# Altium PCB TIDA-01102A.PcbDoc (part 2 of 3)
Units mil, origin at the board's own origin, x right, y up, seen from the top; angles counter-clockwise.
Board outline 4000 x 5050 mil, 4 copper layers (Top Layer, Mid-Layer 1, Mid-Layer 2, Bottom Layer), stack 29.3 mil thick; 176 components, 125 nets, 880 pads, 275 vias.

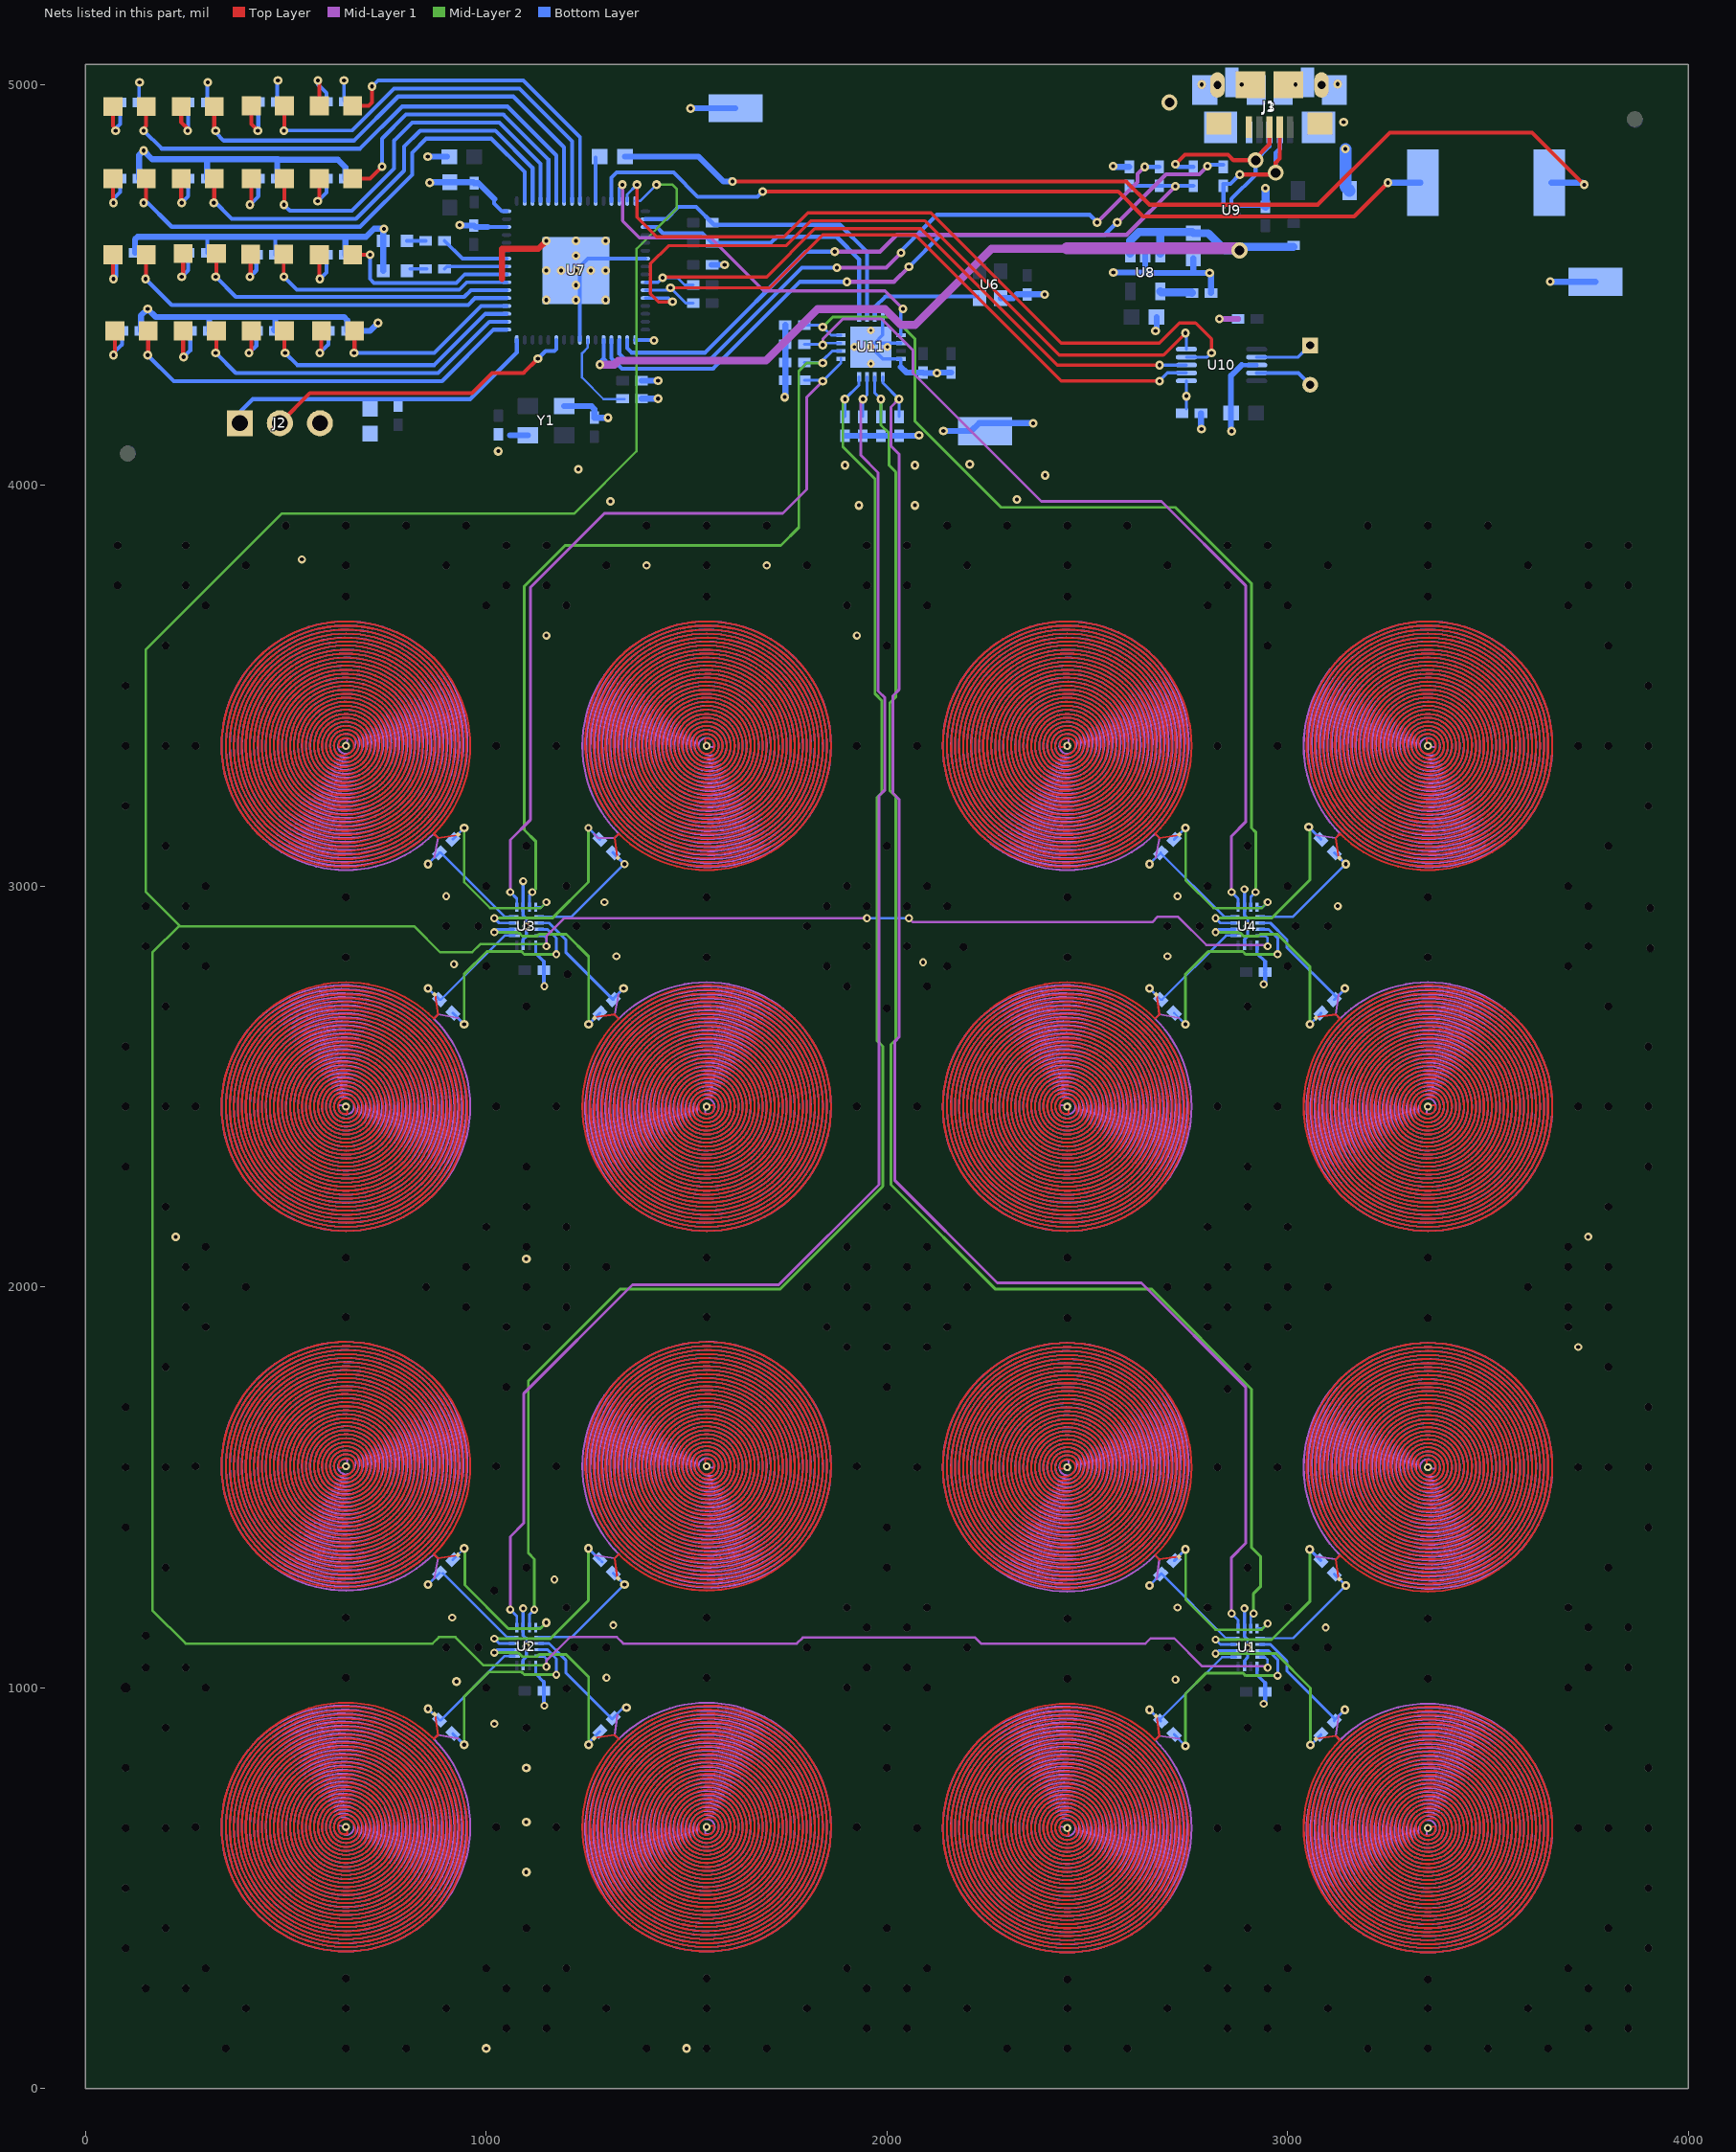
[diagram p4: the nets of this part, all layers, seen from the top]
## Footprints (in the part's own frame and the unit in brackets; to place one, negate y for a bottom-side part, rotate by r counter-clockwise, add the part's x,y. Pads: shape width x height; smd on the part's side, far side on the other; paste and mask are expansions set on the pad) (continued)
PRINTED_COIL_16MM_2_LAYER#7 [mil]
  round 20 hole 10: 2(0,0)
  round 8 smd: 2(355,40)
  Top Layer lines w5: 355,40 325,0 310,0 ccw(c0,0) 0,310 ; -0.05,-310 cw(c-0.6,0.05) -310,20.05 ; -0.21,-310.01 ccw(c-9.95,-0.21) 300,-0.21 ; 300,0 ccw(c0,0) 0,-300 ; -0.11,-300 ccw(c-10.06,-0.11) 0,-300 ; 0.23,-289.99 ccw(c-9.89,-0.28) 280,0.23 ; 290,-0.11 cw(c-10.06,-0.11) 0,-300 ; 290,0 ccw(c0,0) 0,-290 ; 280,0 ccw(c0,0) 0,-280 ; -0.2,-280.01 ccw(c-9.97,-0.2) 270,-0.2 ; 270,0 ccw(c0,0) 0,-270 ; -0.15,-270.01 ccw(c-10.04,-0.15) 260,-0.15 ; 260,0 ccw(c0,0) 0,-260 ; -0.11,-260 ccw(c-10.09,-0.11) 250,-0.11 ; 0.13,-249.99 ccw(c-9.89,-0.3) 240,0.13 ; 250,0 ccw(c0,0) 0,-250 ; 0.13,-239.99 ccw(c-9.92,-0.29) 230,0.13 ; 240,0 ccw(c0,0) 0,-240 ; 0.11,-230 ccw(c-9.92,-0.29) 220,0.11 ; 230,0 ccw(c0,0) 0,-230 ; 0.07,-220 ccw(c-9.91,-0.32) 210,0.07 ; 220,0 ccw(c0,0) 0,-220 ; 210,0 ccw(c0,0) 0,-210 ; -0.17,-210.01 ccw(c-10.07,-0.17) 200,-0.17 ; 0.11,-199.99 ccw(c-10.01,-0.24) 190,0.11 ; 200,0 ccw(c0,0) 0,-200 ; 190,0 ccw(c0,0) 0,-190 ccw(c-9.93,-0.33) 180,0.01 ccw(c0,0) -180,0 ccw(c0.07,0) -4.96,-180 ; -5.04,-180 ccw(c-10.07,0) 170,0 ccw(c0,0) -170,0 ccw(c0.08,0) -4.97,-170 ; -5.03,-170 ccw(c-10.08,0) 160,0 ccw(c0,0) 0,-160 ccw(c-10.04,-0.27) 150,0.01 ccw(c0,0) 0,-150 ; -0.07,-150 ccw(c-10.01,-0.33) 140,-0.07 ; 0.07,-139.99 ccw(c-9.93,-0.42) 130,0.07 ; 140,0 ccw(c0,0) 0,-140 ; 0.02,-130 ccw(c-9.95,-0.43) 120,0.02 ccw(c0,0) 0,-120 ccw(c-10.02,-0.4) 110,0.02 ; 130,0 ccw(c0,0) 0,-130 ; 110,0 ccw(c0,0) 0,-110 ; -0.05,-110 ccw(c-10.02,-0.43) 100,-0.05 ; 0.06,-99.99 ccw(c-10.05,-0.46) 90,0.06 ; 100,0 ccw(c0,0) 0,-100 ; 90,0 ccw(c0,0) 0,-90 ; 0.03,-90 ccw(c-10,-0.56) 80,0.07 ; 80,0 ccw(c0,0) 0,-80 ; -0.11,-80.01 ccw(c-10,-0.63) 70,-0.07 ; 70,0 ccw(c0,0) 0,-70 ccw(c-10,-0.72) 60,0.02 ; 60,0 ccw(c0,0) 0,-60 ; 0.01,-60 ccw(c-10,-0.83) 50,0.01 ccw(c0,0) 0,-50 ; 0.06,-49.99 ccw(c-9.99,-1.01) 40,0.04 ; 40,0 ccw(c0,0) 0,-40 ; -0.02,-40.01 ccw(c-9.96,-1.28) 30,-0.02 ; 30,0 ccw(c0,0) 0,-30 ; -0.04,-30.01 ccw(c-9.95,-1.7) 20,-0.02 ccw(c0,0) -20,0 ccw(c0.76,3) -10.01,-14.99 ; -10,-15 ccw(c-42.14,17.26) -0.01,-0.02 ; -0.05,310 ccw(c-0.59,-0.06) -310,19.95
  Mid-Layer 1 lines w5: 355,-40 325,0 310,0 cw(c0,0) 0,-310 ; -0.05,-310 cw(c-0.59,0.06) -310,-19.95 ; 300,0 cw(c0,0) 0,300 ; 300,0.21 ccw(c-9.95,0.21) -0.21,310.01 ; 290,0 cw(c0,0) 0,290 ; 290,0.11 ccw(c-10.06,0.11) -0.11,300 ; 280,-0.23 ccw(c-9.89,0.28) 0.23,289.99 ; 280,0 cw(c0,0) 0,280 ; 270,0 cw(c0,0) 0,270 ; 270,0.2 ccw(c-9.97,0.2) -0.2,280.01 ; 260,0 cw(c0,0) 0,260 ; 260,0.15 ccw(c-10.04,0.15) -0.15,270.01 ; 250,0 cw(c0,0) 0,250 ; 250,0.11 ccw(c-10.09,0.11) -0.11,260 ; 240,-0.13 ccw(c-9.89,0.3) 0.13,249.99 ; 240,0 cw(c0,0) 0,240 ; 230,-0.13 ccw(c-9.92,0.29) 0.13,239.99 ; 230,0 cw(c0,0) 0,230 ; 220,-0.11 ccw(c-9.92,0.29) 0.11,230 ; 220,0 cw(c0,0) 0,220 ; 210,-0.07 ccw(c-9.91,0.32) 0.07,220 ; 210,0 cw(c0,0) 0,210 ; 200,0 cw(c0,0) 0,200 ; 200,0.17 ccw(c-10.07,0.17) -0.17,210.01 ; 190,-0.11 ccw(c-10.01,0.24) 0.11,199.99 ; 190,0 cw(c0,0) 0,190 cw(c-9.93,0.33) 180,-0.01 ; 180,0 cw(c0,0) -180,0 cw(c0.07,0) -4.96,180 ; 140,0 cw(c0,0) 0,140 ; 140,0.07 ccw(c-10.01,0.33) -0.07,150 ; 130,-0.07 ccw(c-9.93,0.42) 0.07,139.99 ; 130,0 cw(c0,0) 0,130 ; 110,0 cw(c0,0) 0,110 ; 110,-0.02 ccw(c-10.02,0.4) 0.02,120 ccw(c0,0) 120,0 ccw(c-9.95,0.43) 0.02,130 ; 100,0.05 ccw(c-10.02,0.43) -0.05,110 ; 100,0 cw(c0,0) 0,100 ; 90,-0.07 ccw(c-10.05,0.46) 0.06,99.99 ; 90,0 cw(c0,0) 0,90 ; 80,-0.07 ccw(c-10,0.56) 0.03,90 ; 80,0 cw(c0,0) 0,80 ; 70,0 cw(c0,0) 0,70 cw(c-10,0.72) 60,-0.02 ; 70,0.07 ccw(c-10,0.63) -0.11,80.01 ; 60,0 cw(c0,0) 0,60 ; 40,0 cw(c0,0) 0,40 ; 40,-0.04 ccw(c-9.99,1.01) 0.06,49.99 ; 30,0.02 ccw(c-9.96,1.28) -0.02,40.01 ; 30,0 cw(c0,0) 0,30 ; -0.01,0.02 ccw(c-42.14,-17.26) -10,15 ; -10.01,14.99 ccw(c0.76,-3) -20,-0.01 ccw(c0,0) 20,0 ccw(c-9.95,1.7) -0.04,30.01 ; 0,50 ccw(c0,0) 50,0 ccw(c-10,0.83) 0.01,60 ; 0,150 ccw(c0,0) 150,0 ccw(c-10.04,0.27) 0.01,160 ccw(c0,0) 160,0 ccw(c-10.08,0) -5.03,170 ; -4.97,170 ccw(c0.08,0) -170,0 ccw(c0,0) 170,0 ccw(c-10.07,0) -5.04,180 ; -310,-20.05 cw(c-0.6,-0.05) -0.05,310
RGC0064B [mm]
  oval 0.6x0.24 smd mask+0.07: 1(-4.4,3.75) 2(-4.4,3.25) 3(-4.4,2.75) 4(-4.4,2.25) 5(-4.4,1.75) 6(-4.4,1.25) 7(-4.4,0.75) 8(-4.4,0.25) 9(-4.4,-0.25) 10(-4.4,-0.75) 11(-4.4,-1.25) 12(-4.4,-1.75) 13(-4.4,-2.25) 14(-4.4,-2.75) 15(-4.4,-3.25) 16(-4.4,-3.75) 33(4.4,-3.75) 34(4.4,-3.25) 35(4.4,-2.75) 36(4.4,-2.25) 37(4.4,-1.75) 38(4.4,-1.25) 39(4.4,-0.75) 40(4.4,-0.25) 41(4.4,0.25) 42(4.4,0.75) 43(4.4,1.25) 44(4.4,1.75) 45(4.4,2.25) 46(4.4,2.75) 47(4.4,3.25) 48(4.4,3.75)
  oval 0.24x0.6 smd mask+0.07: 17(-3.751,-4.4) 18(-3.251,-4.4) 19(-2.751,-4.4) 20(-2.251,-4.4) 21(-1.75,-4.4) 22(-1.25,-4.4) 23(-0.75,-4.4) 24(-0.25,-4.4) 25(0.25,-4.4) 26(0.75,-4.4) 27(1.25,-4.4) 28(1.75,-4.4) 29(2.251,-4.4) 30(2.751,-4.4) 31(3.251,-4.4) 32(3.751,-4.4) 49(3.751,4.4) 50(3.251,4.4) 51(2.751,4.4) 52(2.251,4.4) 53(1.75,4.4) 54(1.25,4.4) 55(0.75,4.4) 56(0.25,4.4) 57(-0.25,4.4) 58(-0.75,4.4) 59(-1.25,4.4) 60(-1.75,4.4) 61(-2.251,4.4) 62(-2.751,4.4) 63(-3.251,4.4) 64(-3.751,4.4)
  rect 4.25x4.25 smd paste-2.112: 65(0,0)
  silkscreen extent -5.1,-5.1 5.1,5.1, body extent -4.57,-4.57 4.57,4.57, height 1.01
RGH0016A [mm] "QFN, 16-Leads, Body 4x4mm, Pitch 0.5mm, TI Recommended"
  rect 0.6x0.25 smd: 1(-1.9,0.75) 2(-1.9,0.25) 3(-1.9,-0.25) 4(-1.9,-0.75) 9(1.9,-0.75) 10(1.9,-0.25) 11(1.9,0.25) 12(1.9,0.75)
  rect 0.25x0.6 smd: 5(-0.75,-1.9) 6(-0.25,-1.9) 7(0.25,-1.9) 8(0.75,-1.9) 13(0.75,1.9) 14(0.25,1.9) 15(-0.25,1.9) 16(-0.75,1.9)
  rect 2.6x2.6 smd paste-1.3: 17(0,0)
  silkscreen extent -2.17,-2.17 2.17,2.17, body extent -2.05,-2.05 2.05,2.05, height 0.81
RSV0016A [mm] "QFN, 16-Leads, Body 1.8x2.6mm, Pitch 0.4mm, TI Recommended"
  rect 0.7x0.2 smd: 1(-0.75,0.6)
  rect 0.6x0.2 smd: 2(-0.8,0.2) 3(-0.8,-0.2) 4(-0.8,-0.6) 9(0.8,-0.6) 10(0.8,-0.2) 11(0.8,0.2) 12(0.8,0.6)
  rect 0.2x0.6 smd: 5(-0.6,-1.2) 6(-0.2,-1.2) 7(0.2,-1.2) 8(0.6,-1.2) 13(0.6,1.2) 14(0.2,1.2) 15(-0.2,1.2) 16(-0.6,1.2)
  silkscreen extent -1.08,-1.33 1.08,1.45, body extent -0.92,-1.32 0.92,1.33, height 0.56
Samtec_HTSW-103-07-G-S [mm] "Samtec 100mil, 1x3, 230 mil above insulator"
  rect 1.65x1.65 hole 1.016 mask+0: 1(-2.54,0)
  round 1.65 hole 1.016 mask+0: 2(0,0) 3(2.54,0)
  silkscreen extent -4.57,-1.27 3.81,1.27, body extent -3.81,-1.27 3.81,1.27, height 8.38
SOD-123 [mm] "On Semi recommended land pattern"
  rect 0.915x1.22 smd: 1(-1.637,0) 2(1.637,0)
  silkscreen extent -2.74,-1.17 2.03,1.17, body extent -1.93,-0.9 1.93,0.9, height 1.35
Testpoint_Keystone_Miniature [mil] "Miniature SMT test point"
  rect 135x70 smd: 1(0,0)
  silkscreen extent -78,-46 78,45, body extent -52,-20 52,20, height 61
TI_Stacked_Overlay_Small [mil]
  silkscreen extent -418,-98 418,98
XTAL_ABM8 [mm] "Abracon recommended land pattern"
  rect 1.05x1.3 smd: 1(-0.925,1.15) 2(-0.925,-1.15) 3(0.925,-1.15) 4(0.925,1.15)
  silkscreen extent -1.73,1.3 -1.2,2.07, body extent -1.35,-1.7 1.35,1.7, height 0.8

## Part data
C1 C2 C3 C4 C6 C7 C8 C9 C11 C12 C13 C14 C16 C17 C18 C19: "CAP, CERM, 1000 pF, 50 V, +/- 10%, X7R, 0402"
C5 C10 C15 C20 C60 C62 C71: "CAP, CERM, 0.1 µF, 50 V, +/- 10%, X7R, 0402"
C22 C23 C30 C31 C38 C39 C46 C47: "CAP, CERM, 220 pF, 50 V, +/- 10%, X7R, 0402"
C54 C67: "CAP, CERM, 0.1 µF, 16 V, +/- 10%, X7R, 0402"
C61: "CAP, CERM, 0.47 µF, 10 V, +/- 10%, X7R, 0603"
C63 C64: "CAP, CERM, 0.22 µF, 16 V, +/- 10%, X7R, 0402"
C65 C66: "CAP, CERM, 18 pF, 50 V, +/- 5%, C0G/NP0, 0402"
C68: "CAP, CERM, 2.2 µF, 10 V, +/- 10%, X5R, 0603"
C69 C101: "CAP, CERM, 0.01 µF, 16 V, +/- 10%, X7R, 0402"
C70: "CAP, CERM, 10 µF, 10 V, +/- 20%, X5R, 0603"
C72 C74: "CAP, CERM, 10uF, 10V, +/-20%, X5R, 0603"
C73 C75 C102: "CAP, CERM, 1 µF, 10 V, +/- 10%, X5R, 0402"
C78: "CAP, CERM, 2200 pF, 50 V, +/- 10%, X7R, 0603"
D1 D2 D3 D4 D5 D6 D7 D8 D9 D10 D11 D12 D13 D14 D15 D16: "LED, Yellow , SMD"
D17: "LED, Green, SMD"
D18: "LED, Red, SMD"
D19: "Diode, Zener, 5.6 V, 500 mW, SOD-123"
FB1: "Ferrite Bead, 1000 ohm @ 100 MHz, 0.3 A, 0603"
FID1 FID2 FID3 FID4: "Fiducial mark.  There is nothing to buy or mount."
J1: "Connector, Receptacle, USB Mini B, R/A, SMT"
J2: "Header, 100mil, 3x1, Gold, TH"
J3: "Connector, Receptacle, Micro-USB Type B, SMT"
L1 L2 L3 L4 L5 L6 L7 L8 L9 L10 L11 L12 L13 L14 L15 L16: "8.2MM 2-layer Coil 3.5uH"
LBL1: library part THT-14-423-10, "Thermal Transfer Printable Labels, 0.650\" W x 0.200\" H - 10,000 per roll"
Logo1: library part TI_Logo, "Texas Instrument Corporate Signature"
Logo2: library part Pb-Free
Logo3: library part FCC_disclaimer, "FCC_disclaimer"
LS1: "PIEZO BUZZER TRANSDUCER, 4kHz, SMD"
MG1: "10mm Linear Resonant Actuator - 3mm Type, TH"
NT1 NT2 NT3 NT4 NT5 NT6 NT7 NT8 NT9 NT10 NT11 NT12 NT13 NT14 NT15 NT16 NT17 NT18 NT19 NT20 NT21 NT22 NT23 NT24 NT25 NT26 NT27 NT28 NT29 NT30 NT31 NT32: "Single point connection between nets."
R60 R61: "RES, 1.0 k, 5%, 0.063 W, 0402"
R66 R67: "RES, 33, 5%, 0.063 W, 0402"
R68: "RES, 1.0 M, 5%, 0.063 W, 0402"
R69: "RES, 1.5 k, 5%, 0.063 W, 0402"
R70: "RES, 390, 1%, 0.1 W, 0603"
R71: "RES, 33 k, 5%, 0.063 W, 0402"
R95 R96 R97 R98: "RES, 4.7 k, 5%, 0.063 W, 0402"
R101 R102 R103 R104 R105 R106 R107 R108 R109 R110 R111 R112 R113 R114 R115 R116: "RES, 330, 5%, 0.063 W, 0402"
TP1 TP2 TP3: "Test Point, Miniature, SMT"
U1 U2 U3 U4: "Dual SP4T Analog Switch / Multiplexer / Demultiplexer, RSV0016A"
U6: "OSC, 40 MHz, 3.3 V, SMD"
U7: "25 MHz Mixed Signal Microcontroller with 128 KB Flash, 8192 B SRAM and 47 GPIOs, -40 to 85 degC, 64-pin QFN (RGC), Green (RoHS & no Sb/Br)"
U8: "Micropower 150 mA Low-Noise Ultra Low-Dropout Regulator, 5-pin SOT-23, Pb-Free"
U9: "ESD-Protection Array for High-Speed Data Interfaces, 4 Channels, -40 to +85 degC, 6-pin SON (DRY), Green (RoHS & no Sb/Br)"
U10: "Haptic Driver for LRA and ERM With Built-In Library and Smart Loop Architecture, DGS0010A"
U11: "Multi-Channel 12/28-Bit Inductance to Digital Converter with I2C, RGH0016A"
Y1: "Crystal, 24.000MHz, 18pF, SMD"
ZZ1: library part AssemblyNoteLabel
ZZ2 ZZ3 ZZ4: library part AssemblyNote

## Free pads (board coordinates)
  round 20 hole 20 unplated: 0(80,3750) 0(80,3850) 0(100.03,350) 0(100.03,500) 0(100.03,650) 0(100.03,800) 0(100.03,1400) 0(100.03,1550) 0(100.03,1700) 0(100.03,2300) 0(100.03,2450) 0(100.03,2600) 0(100.03,3200) 0(100.03,3350) 0(100.03,3500) 0(150,1130) 0(150.03,250) 0(150.03,1050) 0(150.03,2850) 0(150.03,2950) 0(200.03,400) 0(200.03,650) 0(200.03,900) 0(200.03,1300) 0(200.03,1550) 0(200.03,1800) 0(200.03,2200) 0(200.03,2450) 0(200.03,2700) 0(200.03,3100) 0(200.03,3350) 0(200.03,3600) 0(250.03,250) 0(250.03,1050) 0(250.03,1950) 0(250.03,2050) 0(250.03,2850) 0(250.03,2950) 0(250.03,3750) 0(250.03,3850) 0(275,3350.01) 0(275,1552.51) 0(275.03,2450) 0(275.03,652.5) 0(300.03,300) 0(300.03,1000) 0(300.03,1900) 0(300.03,2100) 0(300.03,2800) 0(300.03,3000) 0(300.03,3700) 0(350.03,100) 0(400.03,200) 0(400.03,2000) 0(400.03,3800) 0(500.03,3900) 0(650,2972.51) 0(650,3722.51) 0(650,1175.01) 0(650,1925.01) 0(650.03,2072.5) 0(650.03,2822.5) 0(650.03,100) 0(650.03,200) 0(650.03,275) 0(650.03,1025) 0(650.03,3800) 0(650.03,3900) 0(800.03,100) 0(800.03,3900) 0(850.03,2000) 0(900.03,200) 0(900.03,1100) 0(900.03,2900) 0(900.03,3800) 0(950.03,1950) 0(950.03,2050) 0(950.03,3900) 0(980.03,1100) 0(980.03,2900) 0(1000,1000) 0(1000.03,300) 0(1000.03,2150) 0(1000.03,2800) 0(1000.03,3000) 0(1000.03,3700) 0(1020,1242) 0(1025,3350.01) 0(1025,1552.51) 0(1025.03,2450) 0(1025.03,652.5) 0(1050.03,150) 0(1050.03,250) 0(1050.03,1750) 0(1050.03,1900) 0(1050.03,3750) 0(1050.03,3850) 0(1100.03,400) 0(1100.03,900) 0(1100.03,1300) 0(1100.03,1850) 0(1100.03,2000) 0(1100.03,2100) 0(1100.03,2200) 0(1100.03,2300) 0(1100.03,2700) 0(1100.03,3100) 0(1150.03,150) 0(1150.03,250) 0(1150.03,1900) 0(1150.03,3750) 0(1150.03,3850) 0(1175.02,2450.02) 0(1175.02,3350.02) 0(1175.02,652.52) 0(1175.02,1552.52) 0(1200.03,300) 0(1200.03,1200) 0(1200.03,1950) 0(1200.03,2050) 0(1200.03,2150) 0(1200.03,3000) 0(1200.03,3700) 0(1201,998) 0(1203.03,2780) 0(1220.03,1100) 0(1225.03,2900) 0(1300.03,200) 0(1300.03,1100) 0(1300.03,2050) 0(1300.03,2900) 0(1300.03,3800) 0(1400.03,100) 0(1400.03,3900) 0(1550.02,2072.52) 0(1550.02,2822.52) 0(1550.02,2972.52) 0(1550.02,3722.52) 0(1550.02,275.02) 0(1550.02,1025.02) 0(1550.02,1175.02) 0(1550.02,1925.02) 0(1550.03,100) 0(1550.03,200) 0(1550.03,3800) 0(1550.03,3900) 0(1700.03,100) 0(1700.03,3900) 0(1800.03,200) 0(1800.03,1100) 0(1800.03,2000) 0(1800.03,2900) 0(1800.03,3800) 0(1850.03,1900) 0(1850.03,2800) 0(1850.03,2950) 0(1900.03,300) 0(1900.03,1000) 0(1900.03,1200) 0(1900.03,1850) 0(1900.03,2000) 0(1900.03,2100) 0(1900.03,2750) 0(1900.03,3000) 0(1900.03,3700) 0(1925.02,2450.02) 0(1925.02,3350.02) 0(1925.02,652.52) 0(1925.02,1552.52) 0(1950.03,150) 0(1950.03,250) 0(1950.03,1050) 0(1950.03,1150) 0(1950.03,1950) 0(1950.03,2050) 0(1950.03,2850) 0(1950.03,2950) 0(1950.03,3750) 0(1950.03,3850) 0(2000.03,400) 0(2000.03,800) 0(2000.03,900) 0(2000.03,1300) 0(2000.03,1400) 0(2000.03,1750) 0(2000.03,1850) 0(2000.03,2200) 0(2000.03,2695) 0(2000.03,3100) 0(2000.03,3600) 0(2050.03,150) 0(2050.03,250) 0(2050.03,1050) 0(2050.03,1150) 0(2050.03,1950) 0(2050.03,2050) 0(2050.03,2850) 0(2050.03,2950) 0(2050.03,3750) 0(2050.03,3850) 0(2075,1550.01) 0(2075.02,3350.02) 0(2075.03,650) 0(2075.03,2450) 0(2100.03,300) 0(2100.03,1000) 0(2100.03,1200) 0(2100.03,1850) 0(2100.03,2000) 0(2100.03,2100) 0(2100.03,2750) 0(2100.03,3000) 0(2100.03,3700) 0(2150.03,1900) 0(2150.03,2800) 0(2150.03,2950) 0(2150.03,3900) 0(2191.03,2848) 0(2200.03,200) 0(2200.03,1100) 0(2200.03,2000) 0(2200.03,3800) 0(2300.03,100) 0(2300.03,3900) 0(2450,1172.51) 0(2450,1922.51) 0(2450.02,2972.52) 0(2450.02,3722.52) 0(2450.03,272.5) 0(2450.03,1022.5) 0(2450.03,2072.5) 0(2450.03,2822.5) 0(2450.03,100) 0(2450.03,200) 0(2450.03,3800) 0(2450.03,3900) 0(2600.03,100) 0(2600.03,3900) 0(2700.03,200) 0(2700.03,1100) 0(2700.03,2000) 0(2700.03,2900) 0(2700.03,3800) 0(2780.03,1100) 0(2780.03,2900) 0(2800.03,300) 0(2800.03,1000) 0(2800.03,1200) 0(2800.03,1900) 0(2800.03,2000) 0(2800.03,2150) 0(2800.03,2800) 0(2800.03,3000) 0(2800.03,3700) 0(2825,1550.01) 0(2825.02,3350.02) 0(2825.03,650) 0(2825.03,2450) 0(2850.03,150) 0(2850.03,250) 0(2850.03,1745) 0(2850.03,1950) 0(2850.03,2050) 0(2850.03,3750) 0(2850.03,3850) 0(2900.03,400) 0(2900.03,900) 0(2900.03,1300) 0(2900.03,1800) 0(2900.03,2200) 0(2900.03,2300) 0(2900.03,2700) 0(2900.03,3100) 0(2950,3600) 0(2950.03,150) 0(2950.03,250) 0(2950.03,1950) 0(2950.03,2050) 0(2950.03,3750) 0(2950.03,3850) 0(2975.01,1550.04) 0(2975.01,3350.04) 0(2975.02,650.02) 0(2975.02,2450.02) 0(3000.03,300) 0(3000.03,1000) 0(3000.03,1200) 0(3000.03,1900) 0(3000.03,2000) 0(3000.03,2150) 0(3000.03,2800) 0(3000.03,3000) 0(3000.03,3700) 0(3020.03,1100) 0(3020.03,2900) 0(3100.03,200) 0(3100.03,1100) 0(3100.03,2000) 0(3100.03,2900) 0(3100.03,3800) 0(3200.03,100) 0(3200.03,3900) 0(3350.01,1172.54) 0(3350.01,1922.54) 0(3350.01,2972.54) 0(3350.01,3722.54) 0(3350.02,272.52) 0(3350.02,1022.52) 0(3350.02,2072.52) 0(3350.02,2822.52) 0(3350.03,100) 0(3350.03,200) 0(3350.03,3800) 0(3350.03,3900) 0(3500.03,100) 0(3500.03,3900) 0(3600.03,200) 0(3600.03,2000) 0(3600.03,3800) 0(3650.03,100) 0(3700,1950) 0(3700,2050) 0(3700.03,300) 0(3700.03,1000) 0(3700.03,1200) 0(3700.03,1900) 0(3700.03,2100) 0(3700.03,2800) 0(3700.03,3000) 0(3700.03,3700) 0(3725.01,1550.04) 0(3725.01,3350.04) 0(3725.02,650.02) 0(3725.02,2450.02) 0(3750.03,150) 0(3750.03,250) 0(3750.03,1050) 0(3750.03,1150) 0(3750.03,2850) 0(3750.03,2950) 0(3750.03,3750) 0(3750.03,3850) 0(3800,1950) 0(3800,2050) 0(3800.03,400) 0(3800.03,650) 0(3800.03,900) 0(3800.03,1300) 0(3800.03,1550) 0(3800.03,1800) 0(3800.03,2200) 0(3800.03,2450) 0(3800.03,2700) 0(3800.03,3100) 0(3800.03,3350) 0(3800.03,3600) 0(3850.03,150) 0(3850.03,250) 0(3850.03,1050) 0(3850.03,1150) 0(3850.03,3750) 0(3850.03,3850) 0(3900.03,350) 0(3900.03,500) 0(3900.03,650) 0(3900.03,800) 0(3900.03,1400) 0(3900.03,1550) 0(3900.03,1700) 0(3900.03,2300) 0(3900.03,2450) 0(3900.03,2600) 0(3900.03,3200) 0(3900.03,3350) 0(3900.03,3500) 0(3905,2845) 0(3905,2945)
  round 25 hole 25 unplated paste+5: 0(100,1000)

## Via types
v1: diameter 22, hole 10, Top Layer to Bottom Layer, tented both sides, 185 vias
v2: diameter 20, hole 10, Top Layer to Bottom Layer, tented both sides, 80 vias
v3: diameter 19.68, hole 7.87, Top Layer to Bottom Layer, tented both sides, 5 vias
v4: diameter 40, hole 24, Top Layer to Bottom Layer, 4 vias
v5: diameter 40, hole 24, Top Layer to Bottom Layer, tented both sides, 1 vias

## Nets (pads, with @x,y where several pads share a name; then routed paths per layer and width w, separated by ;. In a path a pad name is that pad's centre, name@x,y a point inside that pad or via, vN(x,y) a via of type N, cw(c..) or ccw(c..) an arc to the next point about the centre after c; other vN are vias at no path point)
+5V: C68.1 FB1.2 U7.53 U8.1 U8.3 | length 2341.1
  Mid-Layer 1 w20: v1(1283.94,4301.06) 1320,4301.06 1330,4311.06 1698.07,4311.06 1827.01,4440 1995,4440 2035,4400 2070,4400 2190,4520 2190.36,4520 2260.36,4590 2448.59,4590 2449.59,4591
  Mid-Layer 1 w30: 2449.59,4591 2874.59,4591 v5(2879.59,4586)
  Bottom Layer w10: 1292.85,4309.98 U7.53@1292.85,4362.83
  Bottom Layer w20: v1(1283.94,4301.06) 1292.85,4309.98 ; U8.1@2607.19,4578.24 2607.19,4610.41 2628.68,4631.9 2681.99,4631.9 ; U8.3@2681.99,4578.24 2681.99,4631.9 ; FB1.2@3014.59,4594.5 2878.09,4594.5 2869.59,4586 2844.59,4586 2801.6,4628.99 C68.1@2764.59,4628.99 2761.68,4631.9 2681.99,4631.9
AA0: C22.2 U1.5 U11.9 | length 3811.6
  Mid-Layer 1 w7: v1(2030,4215) 2010,4195 2010,4098.07 2030,4078.07 2030,3490 2015,3475 2015,3232 2030,3217 2030,2623 2020,2613 2020,2265 2275,2010 2635,2010 2895,1750 2895,1360 2860,1325 v2(2860,1185)
  Bottom Layer w7: U11.9@1989.53,4270.2 1989.53,4255.47 v1(2030,4215) C22.2@2030,4170.91 ; v2(2860,1185) 2876.38,1168.62 U1.5@2876.38,1147.24
AA1: C30.2 U2.5 U11.11 | length 3803.6
  Mid-Layer 1 w7: v2(1060,1195) 1060,1377.16 1093.27,1410.44 1093.27,1733.27 1365,2005 1730,2005 1980,2255 1980,3225 1995,3240 1995,3470 1978.11,3486.89 1978.11,4031.89 1935,4075 1935,4210 v1(1940,4215)
  Bottom Layer w7: v2(1060,1195) 1076.38,1178.62 U2.5@1076.38,1149.74 ; C30.2@1940,4170.91 v1(1940,4215) 1950.16,4225.16 U11.11@1950.16,4270.2
AA2: C38.2 U3.5 U11.13 | length 2024.6
  Mid-Layer 1 w7: v2(1060,2985) 1060,3115 1110,3165 1110,3745 1295,3930 1740,3930 1800,3990 1800,4220 v1(1840,4260)
  Bottom Layer w7: v2(1060,2985) 1076.38,2968.62 U3.5@1076.38,2947.24 ; C38.2@1793.62,4261.81 1838.19,4261.81 v1(1840,4260) 1885.2,4305.2 U11.13@1885.2,4315.47
AA3: C46.2 U4.5 U11.15 | length 2317.7
  Mid-Layer 1 w7: v1(1840,4350) 1840,4365 1890,4415 1986.61,4415 2065,4336.61 2065,4280 2385,3960 2685,3960 2895,3750 2895,3160 2860,3125 v2(2860,2985)
  Bottom Layer w7: C46.2@1793.62,4351.81 1838.19,4351.81 v1(1840,4350) 1844.84,4354.84 U11.15@1885.2,4354.84 ; v2(2860,2985) 2876.38,2968.62 U4.5@2876.38,2947.24
BB0: C23.2 U1.7 U11.10 | length 3818.9
  Mid-Layer 2 w7: v1(1985,4215) 1985,4150 2005,4130 2005,4050 2021.73,4033.27 2021.73,3471.73 2007,3457 2007,3238 2021.73,3223.27 2021.73,2616.73 2010,2605 2010,2255 2270,1995 2660,1995 2910,1745 2910,1350 2932,1328 2932,1252 2915,1235 v2(2915,1185)
  Bottom Layer w7: U11.10@1969.84,4270.2 1969.84,4230.16 v1(1985,4215) C23.2@1985,4170.91 ; U1.7@2907.87,1147.24 2907.87,1177.87 v2@2910,1180
BB1: C31.2 U2.7 U11.12 | length 3844.2
  Mid-Layer 2 w7: v2(1120,1195) 1120,1321 1105,1336 1105,1765 1335,1995 1734,1995 1990,2251 1990,2600 1975,2615 1975,3220 1987,3232 1987,3463 1970,3480 1970,4016.22 1890,4096.22 1890,4210 v1(1895,4215)
  Bottom Layer w7: U2.7@1107.87,1149.74 1107.87,1182.87 v2(1120,1195) ; C31.2@1895,4170.91 v1(1895,4215) 1930.47,4250.47 U11.12@1930.47,4270.2
BB2: C39.2 U3.7 U11.14 | length 2128.9
  Mid-Layer 2 w7: v2@1117.51,2987.51 1124,2994 1124,3111 1095,3140 1095,3748 1197,3850 1735,3850 1780,3895 1780,4285.18 1799.82,4305 v1(1840,4305)
  Bottom Layer w7: U3.7@1107.87,2947.24 1107.87,2977.87 v2(1115,2985) ; C39.2@1793.62,4306.81 1833.19,4306.81 1835,4305 v1(1840,4305) 1840,4311.64 1863.51,4335.16 U11.14@1885.2,4335.16
BB3: C47.2 U4.7 U11.16 | length 2395.2
  Mid-Layer 2 w7: v1(1840,4395) 1864.8,4419.8 2015.2,4419.8 2031.32,4403.68 2032.03,4403.68 2070,4365.71 2070,4160 2285,3945 2720,3945 2910,3755 2910,3145 2920,3135 v2(2920,2985)
  Bottom Layer w7: C47.2@1793.62,4400 1835,4400 v1(1840,4395) 1860.47,4374.53 U11.16@1885.2,4374.53 ; U4.7@2907.87,2947.24 2907.87,2972.87 v2(2920,2985)
C1: L1.2 NT7.2 NT8.2
C2: L2.2 NT5.2 NT6.2
C3: L3.2 NT3.2 NT4.2
C4: L4.2 NT1.2 NT2.2
C6: L5.2 NT15.2 NT16.2 | length 50.3
  Mid-Layer 1 w5: NT16.2@870.69,1273.19 879.81,1322.69
C7: L6.2 NT13.2 NT14.2
C8: L7.2 NT11.2 NT12.2
C9: L8.2 NT9.2 NT10.2 | length 50.3
  Mid-Layer 1 w5: 879.81,882.31 NT10.2@929.31,873.19
C11: L9.2 NT23.2 NT24.2 | length 50.3
  Mid-Layer 1 w5: NT24.2@870.69,3070.69 879.81,3120.19
C12: L10.2 NT21.2 NT22.2 | length 69.8
  Mid-Layer 1 w5: NT22.2@1269.54,3129.39 1278.93,3120 1320.22,3120 1330.8,3130.58 1330.8,3130.8
C13: L11.2 NT19.2 NT20.2 | length 50.9
  Mid-Layer 1 w5: 1320.19,2679.81 NT20.2@1329.83,2729.83
C14: L12.2 NT17.2 NT18.2 | length 50.3
  Mid-Layer 1 w5: 879.81,2679.81 NT18.2@929.31,2670.69
C16: L13.2 NT31.2 NT32.2 | length 50.3
  Mid-Layer 1 w5: NT32.2@2670.69,3070.69 2679.81,3120.19
C17: L14.2 NT29.2 NT30.2
C18: L15.2 NT27.2 NT28.2 | length 50
  Mid-Layer 1 w5: 3120.19,2679.81 NT28.2@3127.26,2729.31
C19: L16.2 NT25.2 NT26.2 | length 50.3
  Mid-Layer 1 w5: 2679.81,2679.81 NT26.2@2729.31,2670.69
DM: R66.2 U7.52 | length 1783.9
  Mid-Layer 1 w10: v1(1899.88,4507.87) 2017.87,4507.87 v1(2055,4545) ; v1(2574.59,4656) 2576.38,4656 2696.38,4776 2779.59,4776 v1(2799.59,4796)
  Bottom Layer w10: U7.52@1312.54,4362.83 1312.54,4317.46 1338.94,4291.06 1566.06,4291.06 1782.87,4507.87 v1@1894.88,4507.87 ; v1(2055,4545) 2135,4625 2543.59,4625 v1(2574.59,4656) ; v1@2803.21,4799.62 R66.2@2839.59,4799.62
DP: R67.2 R68.2 R69.2 U7.50 | length 1724.9
  Mid-Layer 1 w10: v1(1869.88,4582.87) 1982.87,4582.87 2025,4625 2598.59,4625 v1(2719.59,4746)
  Bottom Layer w10: U7.50@1351.92,4362.83 1351.92,4342 1362.86,4331.06 1546.06,4331.06 1797.87,4582.87 v1(1869.88,4582.87) ; R68.2@2604.59,4747.37 R69.2@2679.59,4747.37 2720.97,4747.37 R67.2@2764.59,4747.37
GND: C5.2 C10.2 C15.2 C20.2 C22.1 C23.1 C30.1 C31.1 C38.1 C39.1 C46.1 C47.1 C54.2 C60.2 C61.2 C62.2 C63.2 C64.1 C65.2 C66.2 C67.2 C68.2 C69.2 C70.2 C71.2 C72.2 C73.1 C74.1 C75.1 C78.1 C101.2 C102.1 D17.2 D18.2 D19.2 J1.5 J1.6 J1.7 J1.8 J1.9 J1.10 J1.11 J2.3 J3.5 J3.6 J3.7 J3.8 J3.9 J3.10 J3.11 J3.12 J3.13 R68.1 R101.1 R102.1 R103.1 R104.1 R105.1 R106.1 R107.1 R108.1 R109.1 R110.1 R111.1 R112.1 R113.1 R114.1 R115.1 R116.1 TP1.1 TP2.1 TP3.1 U1.6 U1.13 U1.15 U2.6 U2.13 U2.15 U3.6 U3.13 U3.15 U4.6 U4.13 U4.15 U6.2 U7.14 U7.16 U7.39 U7.49 U7.56 U7.65 U8.2 U9.3 U10.8 U11.4 U11.6 U11.8 U11.17 Y1.2 Y1.4 | length 7244
  Top Layer w15: 1039.53,4515 1039.53,4590 1130.24,4590 v1(1150.12,4609.88)
  Mid-Layer 1 w15: v1@2783.62,4141.38 v1(2785,4140) ; v1(2830,4415) 2876.38,4415 ; v1@2858.5,4136.5 v1(2860,4135)
  Bottom Layer w8: U2.15@1092.13,1055.26 1092.13,1069.63 1100,1077.5 1100,1122.5 1098.57,1123.93 1098.14,1123.93 1092.13,1129.95 U2.6@1092.13,1149.74 v2(1092.13,1197.87) ; U3.15@1092.13,2852.76 1092.13,2867.13 1100,2875 1100,2920 1098.57,2921.43 1098.14,2921.43 1092.13,2927.44 U3.6@1092.13,2947.24 v2(1092.13,3012.13) ; U2.13@1123.62,1055.26 1123.62,1034.38 1143.62,1014.38 ; U3.13@1123.62,2852.76 1123.62,2831.88 1143.62,2811.88 ; v3(1960,4345) U11.17@1969.84,4354.84 ; U11.4@1989.53,4419.8 1989.53,4374.53 U11.17@1969.84,4354.84 ; U11.6@2034.8,4354.84 U11.17@1969.84,4354.84 ; U1.15@2892.13,1052.76 2892.13,1067.13 2900,1075 2900,1120 2898.57,1121.43 2898.14,1121.43 2892.13,1127.45 U1.6@2892.13,1147.24 v2(2892.13,1197.87) ; U4.15@2892.13,2852.76 2892.13,2867.13 2900,2875 2900,2920 2898.57,2921.43 2898.14,2921.43 2892.13,2927.44 U4.6@2892.13,2947.24 v2(2892.13,2992.13) ; U1.13@2923.62,1052.76 2923.62,1031.88 2943.62,1011.88 ; U4.13@2923.62,2852.76 2923.62,2831.88 2943.62,2811.88
  Bottom Layer w9: R113.1@133.62,4955 133.62,5003.62 v1(135,5005) ; R106.1@303.62,4580 303.62,4618.62 305,4620 ; R114.1@303.62,4955 303.62,5003.62 v1(305,5005) ; R107.1@473.62,4575 473.62,4618.62 475,4620 ; R115.1@478.62,4956.79 478.62,5008.62 v1(480,5010) ; v1(645,5010) 645,4960.43 R116.1@648.62,4956.81 ; 1003.43,4644.33 U7.14@1050.71,4644.33 ; 1019.88,4714.53 1019.88,4702.87 1039.06,4683.7 U7.16@1050.71,4683.7 ; v3(1960,4345) 1989.53,4315.47 U11.8@2034.8,4315.47 2034.8,4295.2
  Bottom Layer w10: v2@1143.62,956.38 C10.2@1143.62,992.5 1143.62,1014.38 ; v2@1143.62,2751.38 C15.2@1143.62,2790 1143.62,2811.88 ; U7.56@1233.78,4362.83 1233.78,4526.22 v1(1223.94,4536.06) 1253.46,4565.59 U7.39@1397.17,4565.59 ; U7.49@1371.61,4362.83 1417.17,4362.83 v1(1418.94,4361.06) ; U9.3@2879.28,4697.81 C67.2@2941.4,4697.81 ; 2885,4300 U10.8@2922.6,4300 ; v2@2943.62,963.62 C5.2@2943.62,990 2943.62,1011.88 ; v2@2943.62,2758.62 C20.2@2943.62,2785 ; C20.2@2943.62,2790 2943.62,2811.88 ; J3.13@3122.5,4998.91 v1(3124.59,5001)
  Bottom Layer w15: R105.1@123.62,4580 123.62,4613.62 130,4620 305,4620 475,4620 700,4620 720,4640 v1(745,4640) 742.93,4637.93 D18.2@742.93,4610 D17.2@742.93,4535 ; R109.1@133.62,4765 133.62,4823.62 v1(145,4835) 166.38,4813.62 305,4813.62 ; R101.1@138.62,4385 138.62,4423.62 v1(155,4440) 175,4420 309.57,4420 ; R110.1@303.62,4765 303.62,4812.24 305,4813.62 ; R102.1@308.62,4385 308.62,4419.06 309.57,4420 ; R103.1@470,4388.62 R103.1@473.62,4385 473.62,4418.62 475,4420 ; R111.1@478.62,4765 478.62,4812.24 ; R108.1@648.62,4575 648.62,4616.38 ; R112.1@648.62,4765 648.62,4793.5 629.88,4812.24 478.62,4812.24 ; v1(730,4405) 710,4385 R104.1@653.62,4385 653.62,4411.38 645,4420 475,4420 ; v1(854.06,4820) C61.2@902.56,4820 ; v1@860.55,4756.5 C72.2@904.06,4756.5 ; C72.2@908.94,4756.02 967.6,4756.02 C62.2@970,4753.62 980.79,4753.62 1019.88,4714.53 ; v1(933.94,4649.53) 935.32,4648.15 C71.2@968.94,4648.15 ; C71.2@972.76,4644.33 1003.43,4644.33 ; 1059.73,4124.65 Y1.2@1103.66,4124.65 ; Y1.4@1194.21,4197.48 1262.52,4197.48 1270,4190 C66.2@1270,4168.62 v1(1303.62,4168.62) ; C64.1@1387.56,4216.06 v1(1428.94,4216.06) ; C63.2@1387.56,4261.06 v1(1428.94,4261.06) ; v1@1519,4941 TP3.1@1622,4941 ; C60.2@1562.76,4550 v1(1595,4550) ; v1(1745,4220) 1746.38,4221.38 C38.1@1746.38,4261.81 C39.1@1746.38,4306.81 C46.1@1746.38,4351.81 C47.1@1746.38,4400 ; C31.1@1895,4123.66 C30.1@1940,4123.66 C23.1@1985,4123.66 C22.1@2030,4123.66 2078.66,4123.66 v1(2080,4125) ; 2034.8,4295.2 2048.62,4281.38 C54.2@2090,4281.38 2091.38,4280 v1(2125,4280) 2126.38,4281.38 C102.1@2160,4281.38 ; v1(2140.95,4135.63) 2210.63,4135.63 2230,4155 v1(2365,4155) ; U6.2@2283.81,4467 2315,4467 2324.38,4476.38 C101.2@2350,4476.38 v1(2393.62,4476.38) v1@2395,4475 ; v1(2565,4531) 2644.59,4531 ; v1@2565.97,4794.62 R68.1@2604.59,4794.62 ; U8.2@2644.59,4578.24 2644.59,4531 ; v1(2670,4385) 2672.99,4387.99 C70.2@2672.99,4420 ; C68.2@2764.59,4566 2764.59,4534.59 2760,4530 ; v1@2783.62,4141.38 C75.1@2783.62,4180 ; C69.2@2808.09,4480.53 C69.2@2808.62,4480 2808.62,4526.38 v1(2805,4530) 2760,4530 ; v1(2830,4415) C73.1@2876.38,4415 ; v1@2858.5,4136.5 C74.1@2858.5,4180 2858.5,4273.5 2885,4300 ; v1(3655,4508) TP1.1@3768,4508 ; 305,4813.62 480,4813.62 478.62,4812.24 ; 309.57,4420 475,4420 ; 2644.59,4531 2645.59,4530 2760,4530
  Bottom Layer w20: C67.2@2941.4,4697.81 C67.2@2944.59,4694.62 v1(2944.59,4741)
  Bottom Layer w30: v1(3144.06,4839.06) 3144.06,4745.41 D19.2@3154.47,4735
  other v1: 1000,100 1500,100 1100,540 1100,665 1100,800 925.66,1015.59 1100,2070 225,2125 1930,3950 2070,3950 1310,3960 2324.37,3965 2395,4025 1230,4040 1895.42,4050 2070,4050 2206.69,4052.59 1030,4085 1150.12,4462.24 1223.94,4462.24 1297.76,4462.24 1223.94,4499.15 1150.12,4536.06 1187.03,4536.06 1260.85,4536.06 1297.76,4536.06 1223.94,4572.97 1223.94,4609.88 1297.76,4609.88 859.06,4755 2564.59,4796 3139.59,4906 1510,4940 2785.3,5000 2885,5000 3020,5000
  other v2: 1020,910 1145,955 2940,960 2720,1020 1300,1025 2900,1100 1100,1102.5 3095,1150 1317.2,1156.16 915,1175 2725,1200 1170,1270 3725,1850 3750,2125 1145,2750 2940,2755 919.4,2805 2090,2810 1325,2825 2700,2825 1100,2900 2900,2900 3125,2950 1295,2960 900,2975 2725,2975 1150,3625 1925,3625 1400,3800 1700,3800 540,3815
  other v3: 1960,4303.66 1918.66,4345 2001.34,4345 1960,4386.34
  other v4: 2705,4955
GPIO1: D1.1 U7.1 | length 1036.4
  Top Layer w10: v1(155,4325) 156.34,4326.34 D1.1@156.34,4385
  Bottom Layer w10: v1(155,4325) 220,4260 890,4260 1018.43,4388.43 U7.1@1050.71,4388.43
GPIO2: D2.1 U7.2 | length 855
  Top Layer w10: v1(325,4330) 326.34,4331.34 D2.1@326.34,4385
  Bottom Layer w10: v1(325,4330) 375,4280 880,4280 1008.11,4408.11 U7.2@1050.71,4408.11
GPIO3: D3.1 U7.3 | length 673.6
  Top Layer w10: D3.1@496.34,4385 496.34,4331.85 v1(498.19,4330)
  Bottom Layer w10: v1(498.19,4330) 528.19,4300 870,4300 997.8,4427.8 U7.3@1050.71,4427.8
GPIO4: D4.1 U7.4 | length 473
  Top Layer w10: 671.34,4341.34 D4.1@671.34,4385
  Bottom Layer w10: v1(670,4330) 870,4330 987.48,4447.48 U7.4@1050.71,4447.48
GPIO5: D5.1 U7.5 | length 995.3
  Top Layer w10: v1(150,4515) 151.34,4516.34 D5.1@151.34,4575
  Bottom Layer w10: v1(150,4515) 215,4450 955,4450 972.17,4467.17 U7.5@1050.71,4467.17
GPIO6: D6.1 U7.6 | length 812.1
  Top Layer w10: v1(325,4520) 326.34,4521.34 D6.1@326.34,4578.19
  Bottom Layer w10: v1(325,4520) 375,4470 945,4470 961.85,4486.85 U7.6@1050.71,4486.85
GPIO7: D7.1 U7.7 | length 633.2
  Top Layer w9: D7.1@494.69,4576.39 494.69,4520.31 v1(495,4520)
  Bottom Layer w9: v1(495,4520) 527.01,4487.99 932.99,4487.99 951.54,4506.54 U7.7@1050.71,4506.54
GPIO8: D8.1 U7.8 | length 457.3
  Top Layer w9: D8.1@666.34,4575 v1(710,4575)
  Bottom Layer w9: v1(710,4575) 710,4515 720,4505 925,4505 946.22,4526.22 U7.8@1050.71,4526.22
GPIO9: D9.1 U7.18 | length 1265.8
  Top Layer w10: v1(145,4705) 151.34,4711.34 D9.1@151.34,4765
  Bottom Layer w10: v1@150,4710 215,4645 685,4645 815,4775 815,4830 850,4865 1012.76,4865 1095.95,4781.8 U7.18@1095.95,4709.29
GPIO10: D10.1 U7.19 | length 1117.4
  Top Layer w10: v1@320,4710 321.34,4711.34 D10.1@321.34,4765
  Bottom Layer w10: v1@320,4710 365,4665 675,4665 795,4785 795,4845 835,4885 1022.76,4885 1115.64,4792.11 U7.19@1115.64,4709.29
  other v1: 320,4705
GPIO11: D11.1 U7.20 | length 972.8
  Top Layer w10: v1(495,4700) 496.34,4701.34 D11.1@496.34,4765
  Bottom Layer w10: v1@500,4695 510,4685 665,4685 770,4790 770,4860 815,4905 1032.76,4905 1135.33,4802.42 U7.20@1135.33,4709.29
GPIO12: D12.1 U7.21 | length 745.9
  Top Layer w10: D12.1@666.34,4765 710,4765 v1(740,4795)
  Bottom Layer w10: v1(740,4795) 740,4865 800,4925 1042.76,4925 1155.02,4812.73 U7.21@1155.02,4709.29
GPIO13: D13.1 U7.22 | length 1313.7
  Top Layer w10: v1@145,4890 151.34,4896.34 D13.1@151.34,4945
  Bottom Layer w10: v1(145,4885) 190,4840 685,4840 790,4945 1052.76,4945 1174.71,4823.04 U7.22@1174.71,4709.29
GPIO14: D14.1 U7.23 | length 1181.3
  Top Layer w10: D14.1@321.34,4945 321.34,4888.66 v1(325,4885)
  Bottom Layer w10: v1@325,4890 v1(325,4885) 325,4880 345,4860 670,4860 780,4970 1067.76,4970 1194.4,4843.35 U7.23@1194.4,4709.29
GPIO15: D15.1 U7.24 | length 1028.7
  Top Layer w9: v1(495,4885) 496.34,4886.34 D15.1@496.34,4946.79
  Bottom Layer w9: v1(495,4885) 665,4885 770,4990 1082.76,4990 1214.09,4858.66 U7.24@1214.09,4709.29
GPIO16: D16.1 U7.25 | length 867.1
  Top Layer w9: D16.1@676.22,4941.81 D16.1@681.81,4941.81 ; D16.1@685,4965.47 D16.1@666.34,4946.81 706.81,4946.81 715,4955 v1(715,4995)
  Bottom Layer w9: v1(715,4995) 730,5010 1092.76,5010 1233.78,4868.97 U7.25@1233.78,4709.29
JTAG_RST: C78.2 J2.1 R71.2 U7.64 | length 810.9
  Bottom Layer w10: J2.1@387.52,4155 387.52,4185 417.52,4215 960,4215 1076.3,4331.3 U7.64@1076.26,4362.83
JTAG_TEST: J2.2 U7.59 | length 789.3
  Top Layer w10: J2.2@485,4155 560,4230 605,4230 965,4230 1015,4280 1092.87,4280 v1(1128.94,4316.06)
  Bottom Layer w10: v1(1128.94,4316.06) 1147.94,4335.06 1169.94,4335.06 1174.71,4339.84 U7.59@1174.71,4362.83
LDC_INT: U7.30 U11.5 | length 992.7
  Mid-Layer 1 w8: v1(1340,4750) 1340,4660 1382.13,4617.87 1560,4617.87 1692.87,4485 1995,4485 v1(2040,4440)
  Bottom Layer w8: U7.30@1332.23,4709.29 1332.23,4742.23 v1(1340,4750) ; U11.5@2034.8,4374.53 2034.8,4434.8 v1(2040,4440)
NetC1_1: C1.1 NT8.1 U1.4 | length 292.5
  Bottom Layer w6: C1.1@2684.69,1284.69 2845.76,1123.62 U1.4@2868.5,1123.62
  Bottom Layer w7: v1(2655,1255) C1.1@2684.69,1284.69
NetC1_2: C1.2 NT7.1 U1.8 | length 439
  Mid-Layer 2 w6: v1(2745,1345) 2745,1220 2820,1145 2935,1145 v2(2950,1160)
  Bottom Layer w7: C1.2@2716.7,1316.7 v1(2745,1345) ; U1.8@2923.62,1147.24 2937.24,1147.24 v2(2950,1160)
NetC2_1: C2.1 NT6.1 U1.3 | length 497.9
  Mid-Layer 2 w7: v2(2820,1120) 2960,1120 3055,1215 v1(3055,1345)
  Bottom Layer w7: v2(2820,1120) 2832.13,1107.87 U1.3@2868.5,1107.87 ; v1(3055,1345) C2.1@3083.3,1316.7
NetC2_2: C2.2 NT5.1 U1.9 | length 307.9
  Bottom Layer w5: U1.9@2931.5,1123.62 3013.62,1123.62 v1(3145,1255)
  Bottom Layer w7: C2.2@3116.7,1283.3 v1(3145,1255)
NetC3_1: C3.1 NT4.1 U1.10 | length 315.5
  Bottom Layer w7: U1.10@2931.5,1107.87 2957.13,1107.87 2998.41,1066.59 2998.41,1041.59 C3.1@3116.7,923.3 ; C3.1@3116.7,916.7 3116.7,918.75 v1(3142.95,945)
NetC3_2: C3.2 NT3.1 U1.2 | length 503.4
  Mid-Layer 2 w7: v2(2820,1085) 2971,1085 3056.46,999.54 v1(3056.46,857.39)
  Bottom Layer w7: v2(2820,1085) 2827.13,1092.13 U1.2@2868.5,1092.13 ; v1(3056.46,857.39) 3057.99,857.39 3083.3,882.7 C3.2@3083.3,883.3
NetC4_1: C4.1 NT2.1 U1.11 | length 516.9
  Mid-Layer 2 w7: v1(2745,855) 2745,984.99 2796.76,1036.75 2888.25,1036.75 2895,1030 v2(2975,1030)
  Bottom Layer w7: C4.1@2716.7,883.3 v1(2745,855) ; U1.11@2931.5,1092.13 2952.87,1092.13 2975,1070 v2(2975,1030)
NetC4_2: C4.2 NT1.1 U1.1 | length 290.6
  Bottom Layer w6: C4.2@2683.3,923.3 2836.38,1076.38 U1.1@2870.47,1076.38
  Bottom Layer w7: v1(2655,945) C4.2@2683.3,916.7
NetC6_1: C6.1 NT16.1 U2.4 | length 283
  Bottom Layer w6: C6.1@891.7,1285.8 1051.38,1126.12 U2.4@1068.5,1126.12
  Bottom Layer w7: v1(855,1257.5) C6.1@883.3,1285.8
NetC6_2: C6.2 NT15.1 U2.8 | length 418.5
  Mid-Layer 2 w7: v1(945,1347.5) 946.49,1346.01 946.49,1256.01 1055,1147.5 1135,1147.5 v1(1150,1162.5)
  Bottom Layer w6: C6.2@916.7,1319.2 v1(945,1347.5) ; U2.8@1123.62,1149.74 1137.24,1149.74 v1(1150,1162.5)
NetC7_1: C7.1 NT14.1 U2.3 | length 499.3
  Mid-Layer 2 w7: v2(1020,1122.5) 1160,1122.5 1255,1217.5 v1(1255,1347.5)
  Bottom Layer w7: v2(1020,1122.5) 1032.13,1110.37 U2.3@1068.5,1110.37 ; v1(1255,1347.5) C7.1@1283.3,1319.2 ; C7.1@1288.28,1314.22 C7.1@1289.31,1313.19
NetC7_2: C7.2 NT13.1 U2.9 | length 307.9
  Bottom Layer w6: U2.9@1131.5,1126.12 1213.62,1126.12 v1(1345,1257.5)
  Bottom Layer w7: C7.2@1316.7,1285.8 v1(1345,1257.5)
NetC8_1: C8.1 NT12.1 U2.10 | length 323.3
  Bottom Layer w7: U2.10@1131.5,1110.37 1157.13,1110.37 1198.41,1069.09 1198.41,1037.5 C8.1@1314.2,921.7 ; C8.1@1316.7,924.2 1342.5,950 v1(1350,950)
NetC8_2: C8.2 NT11.1 U2.2 | length 530.5
  Mid-Layer 2 w7: v2(1020,1087.5) 1080,1087.5 1090,1077.5 1126.42,1077.5 1131.42,1082.5 1200,1082.5 1255.6,1026.9 v1(1255.6,857.5)
  Bottom Layer w7: v2(1020,1087.5) 1027.13,1094.63 U2.2@1068.5,1094.63 ; v1(1255.6,857.5) 1255.6,863.1 C8.2@1283.3,890.8
NetC9_1: C9.1 NT10.1 U2.11 | length 541.7
  Mid-Layer 2 w7: v1(945,857.5) 945,945 945,977.5 ; 945,960 945,977.5 ; v2(1175,1032.5) 1095,1032.5 1088.25,1039.25 1006.75,1039.25 945,977.5
  Bottom Layer w7: C9.1@924.85,875.99 916.7,884.13 C9.1@916.7,885.8 v1(945,857.5) ; U2.11@1131.5,1094.63 1152.87,1094.63 1175,1072.5 v2(1175,1032.5)
NetC9_2: C9.2 NT9.1 U2.1 | length 289.9
  Bottom Layer w6: C9.2@886.7,919.2 1046.38,1078.88 U2.1@1070.47,1078.88
  Bottom Layer w7: v1(855,947.5) C9.2@883.3,919.2
NetC11_1: C11.1 NT24.1 U3.4 | length 288
  Bottom Layer w6: v1(855,3055) C11.1@883.3,3083.3 ; C11.1@886.7,3083.3 1046.38,2923.62 U3.4@1068.5,2923.62
NetC11_2: C11.2 NT23.1 U3.8 | length 444.8
  Mid-Layer 2 w6: v1(945,3145) 945,3010 1010,2945 1135,2945 v2(1150,2960)
  Bottom Layer w6: C11.2@916.7,3116.7 v1(945,3145) ; U3.8@1123.62,2947.24 1137.24,2947.24 v2(1150,2960)
NetC12_1: C12.1 NT22.1 U3.3 | length 500.8
  Mid-Layer 2 w7: v2(1020,2920) 1165,2920 1255,3010 v2(1255,3145)
  Bottom Layer w7: v2(1020,2920) 1032.13,2907.87 U3.3@1068.5,2907.87 ; v2(1255,3145) C12.1@1283.3,3116.7
NetC12_2: C12.2 NT21.1 U3.9 | length 307.9
  Bottom Layer w6: U3.9@1131.5,2923.62 1213.62,2923.62 v2(1345,3055)
  Bottom Layer w8: C12.2@1316.7,3083.3 v2(1345,3055)
NetC13_1: C13.1 NT20.1 U3.10 | length 322.1
  Bottom Layer w7: U3.10@1131.5,2907.87 1157.13,2907.87 1198.41,2866.59 1198.41,2835 C13.1@1316.7,2716.7 1316.7,2718.75 v1(1342.95,2745)
NetC13_2: C13.2 NT19.1 U3.2 | length 525.5
  Mid-Layer 2 w7: v2(1020,2885) 1080,2885 1090,2875 1126.42,2875 1131.42,2880 1200,2880 1255.6,2824.4 v1(1255.6,2655)
  Bottom Layer w7: v2(1020,2885) 1027.13,2892.13 U3.2@1068.5,2892.13 ; v1(1255.6,2655) 1283.3,2682.7 C13.2@1283.3,2683.3
NetC14_1: C14.1 NT18.1 U3.11 | length 514
  Mid-Layer 2 w7: v1(945,2655) 945,2780 1001.75,2836.75 1088.25,2836.75 1095,2830 v2(1175,2830)
  Bottom Layer w7: C14.1@916.7,2683.3 v1(945,2655) ; U3.11@1131.5,2892.13 1152.87,2892.13 1175,2870 v2(1175,2830)
NetC14_2: C14.2 NT17.1 U3.1 | length 293.3
  Bottom Layer w6: C14.2@883.3,2716.7 886.7,2716.7 1046.38,2876.38 U3.1@1070.47,2876.38
  Bottom Layer w7: v1(855,2745) C14.2@883.3,2716.7
NetC16_1: C16.1 NT32.1 U4.4 | length 290.7
  Bottom Layer w6: v1(2655,3055) C16.1@2683.3,3083.3 ; C16.1@2683.3,3081.7 2841.38,2923.62 U4.4@2868.5,2923.62
NetC16_2: C16.2 NT31.1 U4.8 | length 441.9
  Mid-Layer 2 w6: v1(2745,3145) 2745,3015 2815,2945 2935,2945 v2(2950,2960)
  Bottom Layer w6: U4.8@2923.62,2947.24 2937.24,2947.24 v2(2950,2960)
  Bottom Layer w7: C16.2@2716.7,3116.7 v1(2745,3145)
NetC17_1: C17.1 NT30.1 U4.3 | length 501.4
  Mid-Layer 2 w7: v2(2820,2920) 2960,2920 3055,3015 v1@3055,3145
  Bottom Layer w7: v2(2820,2920) 2832.13,2907.87 U4.3@2868.5,2907.87 ; v1(3052.5,3147.5) C17.1@3083.3,3116.7
NetC17_2: C17.2 NT29.1 U4.9 | length 307.9
  Bottom Layer w6: U4.9@2931.5,2923.62 3013.62,2923.62 v1(3145,3055)
  Bottom Layer w7: C17.2@3116.7,3083.3 v1(3145,3055)
NetC18_1: C18.1 NT28.1 U4.10 | length 318.7
  Bottom Layer w7: U4.10@2931.5,2907.87 2957.13,2907.87 2998.41,2866.59 2998.41,2846.59 C18.1@3122.5,2722.5 ; C18.1@3116.7,2716.7 C18.1@3122.5,2722.5 ; v1(3142.95,2745) 3142.95,2742.95 C18.1@3122.5,2722.5
NetC18_2: C18.2 NT27.1 U4.2 | length 510.8
  Mid-Layer 2 w7: v2(2820,2885) 2880,2885 2890,2875 2926.42,2875 2931.42,2880 2975,2880 3055.6,2799.4 v1(3055.6,2655)
  Bottom Layer w7: v2(2820,2885) 2827.13,2892.13 U4.2@2868.5,2892.13 ; v1(3055.6,2655) 3083.3,2682.7 C18.2@3083.3,2683.3
NetC19_1: C19.1 NT26.1 U4.11 | length 514
  Mid-Layer 2 w7: v1(2745,2655) 2745,2780 2801.75,2836.75 2888.25,2836.75 2895,2830 v2(2975,2830)
  Bottom Layer w6: C19.1@2716.7,2683.3 v1(2745,2655)
  Bottom Layer w7: U4.11@2931.5,2892.13 2952.87,2892.13 2975,2870 v2(2975,2830)
NetC19_2: C19.2 NT25.1 U4.1 | length 289.9
  Bottom Layer w6: v1(2655,2745) C19.2@2683.3,2716.7 ; C19.2@2686.7,2716.7 2846.38,2876.38 U4.1@2870.47,2876.38
NetC64_2: C64.2 U7.55 | length 228.7
  Bottom Layer w6: U7.55@1253.47,4362.83 1253.47,4344.06 1238.94,4329.53 1238.94,4268.82 1292.69,4215.06 C64.2@1345.32,4215.06
NetC69_1: C69.1 U8.4 | length 80.9
  Bottom Layer w20: U8.4@2681.99,4483.75 2684.75,4481 2760.38,4481 C69.1@2761.38,4480
NetC75_2: C75.2 U10.1 | length 69.6
  Bottom Layer w8: C75.2@2747.4,4191.02 v1(2747.4,4222.4) U10.1@2747.4,4260.63
NetD1_2: D1.2 R101.2 | length 120.4
  Top Layer w10: v1@70,4330 73.66,4333.66 D1.2@73.66,4385
  Bottom Layer w10: v1@70,4330 91.38,4351.38 R101.2@91.38,4385
  other v1: 70,4325
NetD2_2: D2.2 R102.2 | length 137.3
  Top Layer w10: D2.2@243.66,4385 243.66,4321.34 v1(245,4320)
  Bottom Layer w10: v1(245,4320) 261.38,4336.38 R102.2@261.38,4385
NetD3_2: D3.2 R103.2 | length 119.8
  Top Layer w10: v1(408.19,4330) 413.66,4335.47 D3.2@413.66,4385
  Bottom Layer w10: v1(408.19,4330) 426.38,4348.19 R103.2@426.38,4385
NetD4_2: D4.2 R104.2 | length 120.4
  Top Layer w10: v1(585,4330) 588.66,4333.66 D4.2@588.66,4385
  Bottom Layer w10: v1(585,4330) 606.38,4351.38 R104.2@606.38,4385
NetD5_2: D5.2 R105.2 | length 128.2
  Top Layer w10: D5.2@68.66,4575 68.66,4516.34 v1(70,4515)
  Bottom Layer w10: v1(70,4515) 76.38,4521.38 R105.2@76.38,4580
NetD6_2: D6.2 R106.2 | length 126.5
  Top Layer w10: v1(240,4520) 243.66,4523.66 D6.2@243.66,4578.19
  Bottom Layer w10: v1(240,4520) 256.38,4536.38 R106.2@256.38,4580
NetD7_2: D7.2 R107.2 | length 119
  Top Layer w10: v1(410,4520) 412.01,4522.01 D7.2@412.01,4576.39
  Bottom Layer w10: v1(410,4520) 426.38,4536.38 R107.2@426.38,4575
NetD8_2: D8.2 R108.2 | length 127.3
  Top Layer w10: D8.2@583.66,4575 583.66,4516.34 v1(585,4515)
  Bottom Layer w10: v1(585,4515) 601.38,4531.38 R108.2@601.38,4575
NetD9_2: D9.2 R109.2 | length 117.3
  Top Layer w10: D9.2@68.66,4765 68.66,4706.34 v1(70,4705)
  Bottom Layer w10: v1@70,4715 86.38,4731.38 R109.2@86.38,4765
NetD10_2: D10.2 R110.2 | length 115.4
  Top Layer w10: 238.66,4716.34 D10.2@238.66,4765
  Bottom Layer w10: v1(240,4705) 256.38,4721.38 R110.2@256.38,4765
NetD11_2: D11.2 R111.2 | length 140.4
  Top Layer w10: v1(410,4700) 413.66,4703.66 D11.2@413.66,4765
  Bottom Layer w10: v1(410,4700) 431.38,4721.38 R111.2@431.38,4765
NetD12_2: D12.2 R112.2 | length 122.8
  Top Layer w10: v1(579.53,4708.99) 583.66,4713.12 D12.2@583.66,4765
  Bottom Layer w10: v1(579.53,4708.99) 601.38,4730.84 R112.2@601.38,4765
NetD13_2: D13.2 R113.2 | length 127.3
  Top Layer w10: D13.2@68.66,4945 68.66,4896.34 v1@75,4890
  Bottom Layer w10: v1@75,4890 86.38,4901.38 R113.2@86.38,4955
  other v1: 75,4885
NetD14_2: D14.2 R114.2 | length 127.3
  Top Layer w10: D14.2@238.66,4945 238.66,4906.34 v1@255,4890
  Bottom Layer w10: v1@255,4890 256.38,4891.38 R114.2@256.38,4955
  other v1: 255,4885
NetD15_2: D15.2 R115.2 | length 140.9
  Top Layer w10: D15.2@413.66,4946.79 413.66,4901.34 v1(430,4885)
  Bottom Layer w10: v1(430,4885) 431.38,4886.38 R115.2@431.38,4956.79
NetD16_2: D16.2 R116.2 | length 116.7
  Top Layer w10: v1(580,5010) 583.66,5006.34 D16.2@583.66,4946.81
  Bottom Layer w10: v1@580,5000 601.38,4978.62 R116.2@601.38,4956.81
NetD17_1: D17.1 R60.1 | length 41.9
  Bottom Layer w9: D17.1@810,4540 R60.1@851.85,4540
NetD18_1: D18.1 R61.1 | length 46.9
  Bottom Layer w9: D18.1@801.99,4610 R61.1@848.84,4610
NetJ1_2: J1.2 J3.2 R66.1 U9.1 | length 410.2
  Top Layer w10: v1(2880.25,4775.25) 2965.25,4775.25 v4(2970,4780) 2970,4805 2980.18,4815.18 J1.2@2980.18,4893.6
  Bottom Layer w10: U9.1@2839.9,4696.82 2839.9,4752.06 2839.59,4752.37 2857.37,4752.37 v1(2880.25,4775.25) ; v4(2970,4780) 2970,4829.41 2980.59,4840 J3.2@2980.59,4870.49
NetJ1_3: J1.3 J3.3 R67.1 U9.2 | length 563.9
  Top Layer w10: v1(2719.59,4801) 2743.59,4825 2850.97,4825 2865,4810.97 v4(2920,4810.97) 2920,4816.41 2954.59,4851 J1.3@2954.59,4893.6
  Bottom Layer w10: v1@2725.97,4794.62 R67.1@2764.59,4794.62 ; U9.2@2859.59,4697.81 2859.59,4714.59 2920,4775 v4(2920,4810.97) 2955,4845.97 J3.3@2955,4870.49
NetLS1_1: LS1.1 R70.2 | length 2660.3
  Top Layer w10: v1(1614.88,4757.87) 2597.13,4757.87 2655,4700 3075,4700 3255,4880 3610,4880 v1(3740,4750)
  Bottom Layer w15: R70.2@1346.5,4820 1530,4820 1592.13,4757.87 v1(1614.88,4757.87) v1@1611.38,4761.38 ; LS1.1@3658.39,4755 3735,4755 v1(3740,4750)
NetLS1_2: LS1.2 U7.29 | length 2173.4
  Top Layer w10: v1(1689.88,4732.87) 2577.13,4732.87 2639,4671 3166,4671 v1(3250,4755)
  Bottom Layer w10: U7.29@1312.54,4709.29 1312.54,4767.54 1325.37,4780.37 1467.39,4780.37 1527.76,4720 1677.01,4720 v1(1689.88,4732.87)
  Bottom Layer w15: v1(3250,4755) LS1.2@3331.61,4755
NetMG1_1: MG1.1 U10.7 | length 145.9
  Bottom Layer w8: U10.7@2922.6,4319.69 3026.77,4319.69 MG1.1@3056.3,4349.21
NetMG1_2: MG1.2 U10.9 | length 145.9
  Bottom Layer w9: U10.9@2922.6,4280.31 3026.77,4280.31 MG1.2@3056.3,4250.79
NetR60_2: R60.2 U7.9 | length 157.1
  Bottom Layer w9: R60.2@896.08,4540 901.99,4545.91 U7.9@1050.71,4545.91
NetR61_2: R61.2 U7.10 | length 173
  Bottom Layer w9: R61.2@896.08,4610 940.49,4565.59 U7.10@1050.71,4565.59
NetR70_1: R70.1 U7.27 | length 108.3
  Bottom Layer w10: U7.27@1273.16,4709.29 1273.16,4760.29 R70.1@1273.16,4817.61
NetR97_2: R97.2 U7.42 U10.3 | length 1630.3
  Top Layer w8: v1(1439.88,4517.87) 1442.01,4520 1700,4520 1820,4640 2085,4640 2425,4300 v1(2680,4300)
  Bottom Layer w7: v1(1439.88,4517.87) 1477.13,4517.87 1495,4500 R97.2@1516.38,4500
  Bottom Layer w8: U7.42@1397.17,4506.54 1428.54,4506.54 v1(1439.88,4517.87) ; v1(2680,4300) U10.3@2747.4,4300
NetR98_2: R98.2 U7.43 U10.2 | length 1639.2
  Top Layer w8: v1(1459.88,4492.87) 1707.87,4492.87 1840,4625 2070,4625 2435,4260 v1(2680,4260)
  Bottom Layer w7: v1(1459.88,4492.87) 1497.76,4455 R98.2@1516.38,4455
  Bottom Layer w8: U7.43@1397.17,4486.85 1453.86,4486.85 v1(1459.88,4492.87) ; v1(2680,4260) 2700.31,4280.31 U10.2@2747.4,4280.31
NetU6_3: U6.3 U11.3 | length 292.4
  Bottom Layer w10: U11.3@1969.84,4419.8 1969.84,4444.84 1996.54,4471.54 U6.3@2226.12,4471.54
NetU7_31: U7.31 U10.4 | length 1884.6
  Top Layer w8: v1(1376.16,4750) 1376.16,4668.84 1425,4620 1742.7,4620 1802.7,4680 2110,4680 2435,4355 2680,4355 2730,4405 2770,4405 2810,4365 v1(2810,4330)
  Bottom Layer w7: U7.31@1351.92,4709.29 1351.92,4725.76 v1(1376.16,4750)
  Bottom Layer w8: U10.4@2747.4,4319.69 2799.68,4319.69 v1(2810,4330)
NetU7_44: U7.44 U10.5 | length 1792.5
  Top Layer w8: v1(1464.88,4457.87) 1429.88,4457.87 1409.88,4477.87 1409.88,4552.87 1454.88,4597.87 1747.87,4597.87 1810,4660 2095,4660 2430,4325 2690,4325 v1(2745,4380)
  Bottom Layer w8: U7.44@1397.17,4467.17 1455.59,4467.17 v1(1464.88,4457.87) ; v1(2745,4380) 2747.4,4377.6 U10.5@2747.4,4339.37
PUR: R69.1 U7.51 | length 1620
  Mid-Layer 1 w10: v1(1874.88,4542.87) 1997.87,4542.87 v1(2035,4580) ; v1(2524.59,4656) 2625.42,4756.82 2625.42,4776.82 v1(2643.21,4794.62)
  Bottom Layer w10: U7.51@1332.23,4362.83 1332.23,4327.77 1348.94,4311.06 1556.06,4311.06 1787.87,4542.87 v1(1874.88,4542.87) ; v1(2035,4580) 2035,4585 2125,4675 2505.59,4675 v1(2524.59,4656) ; v1(2643.21,4794.62) R69.1@2679.59,4794.62
SCL: R96.2 U7.35 U11.1 | length 723.1
  Bottom Layer w10: U7.35@1397.17,4644.33 1425.67,4644.33 1440.82,4629.18 1539.44,4629.18 R96.2@1563.62,4605 1710,4605 1725,4620 1874.33,4620 1930.47,4563.86 U11.1@1930.47,4419.8
SDA: R95.2 U7.34 U11.2 | length 775.2
  Bottom Layer w10: U7.34@1397.17,4664.02 1449.02,4664.02 1480,4695 1523.62,4695 1568.62,4650 1882.76,4650 1950.16,4582.6 U11.2@1950.16,4419.8
SS0: U1.12 U2.12 U3.12 U4.12 U7.32 | length 10649.4
  Mid-Layer 1 w6: v2(1150,1052.5) 1150,1067 1209,1126 1326,1126 1342,1110 1775,1110 1790,1125 2220,1125 2235,1110 2645,1110 2658,1123 2717,1123 2786.75,1053.25 v2@2946.75,1053.25 ; v2@1150,2852.5 1150,2875 1195,2920 v2(1950,2920) ; v2(2055,2920) 2065,2910 2662,2910 2676,2924 2726,2924 2796.75,2853.25 v2@2946.75,2853.25
  Mid-Layer 2 w6: v2(1150,1052.5) 1146.75,1055.75 993.25,1055.75 923,1126 882,1126 866,1110 250,1110 167.03,1192.97 167.03,2834.03 234.5,2901.5 ; v2(1150,2850) 1145,2855 985,2855 965,2835 885,2835 820,2900 236,2900 234.5,2901.5 ; v1(1425,4750) 1465,4750 1475,4740 1475,4690 1375,4590 1375,4085 1220,3930 490,3930 150,3590 150,2986 234.5,2901.5
  Bottom Layer w6: U2.12@1131.5,1078.88 1143.62,1078.88 1150,1072.5 v2(1150,1052.5) ; U3.12@1131.5,2876.38 1143.62,2876.38 1150,2870 v2(1150,2850) ; U7.32@1371.61,4709.29 1384.29,4709.29 v1(1425,4750) ; v2(1950,2920) v2(2055,2920) ; U1.12@2931.5,1076.38 2943.62,1076.38 2950,1070 v2(2950,1050) ; U4.12@2931.5,2876.38 2943.62,2876.38 2950,2870 v2(2950,2850)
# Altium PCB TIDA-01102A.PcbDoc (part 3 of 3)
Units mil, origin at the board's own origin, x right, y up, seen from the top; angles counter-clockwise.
Board outline 4000 x 5050 mil, 4 copper layers (Top Layer, Mid-Layer 1, Mid-Layer 2, Bottom Layer), stack 29.3 mil thick; 176 components, 125 nets, 880 pads, 275 vias.

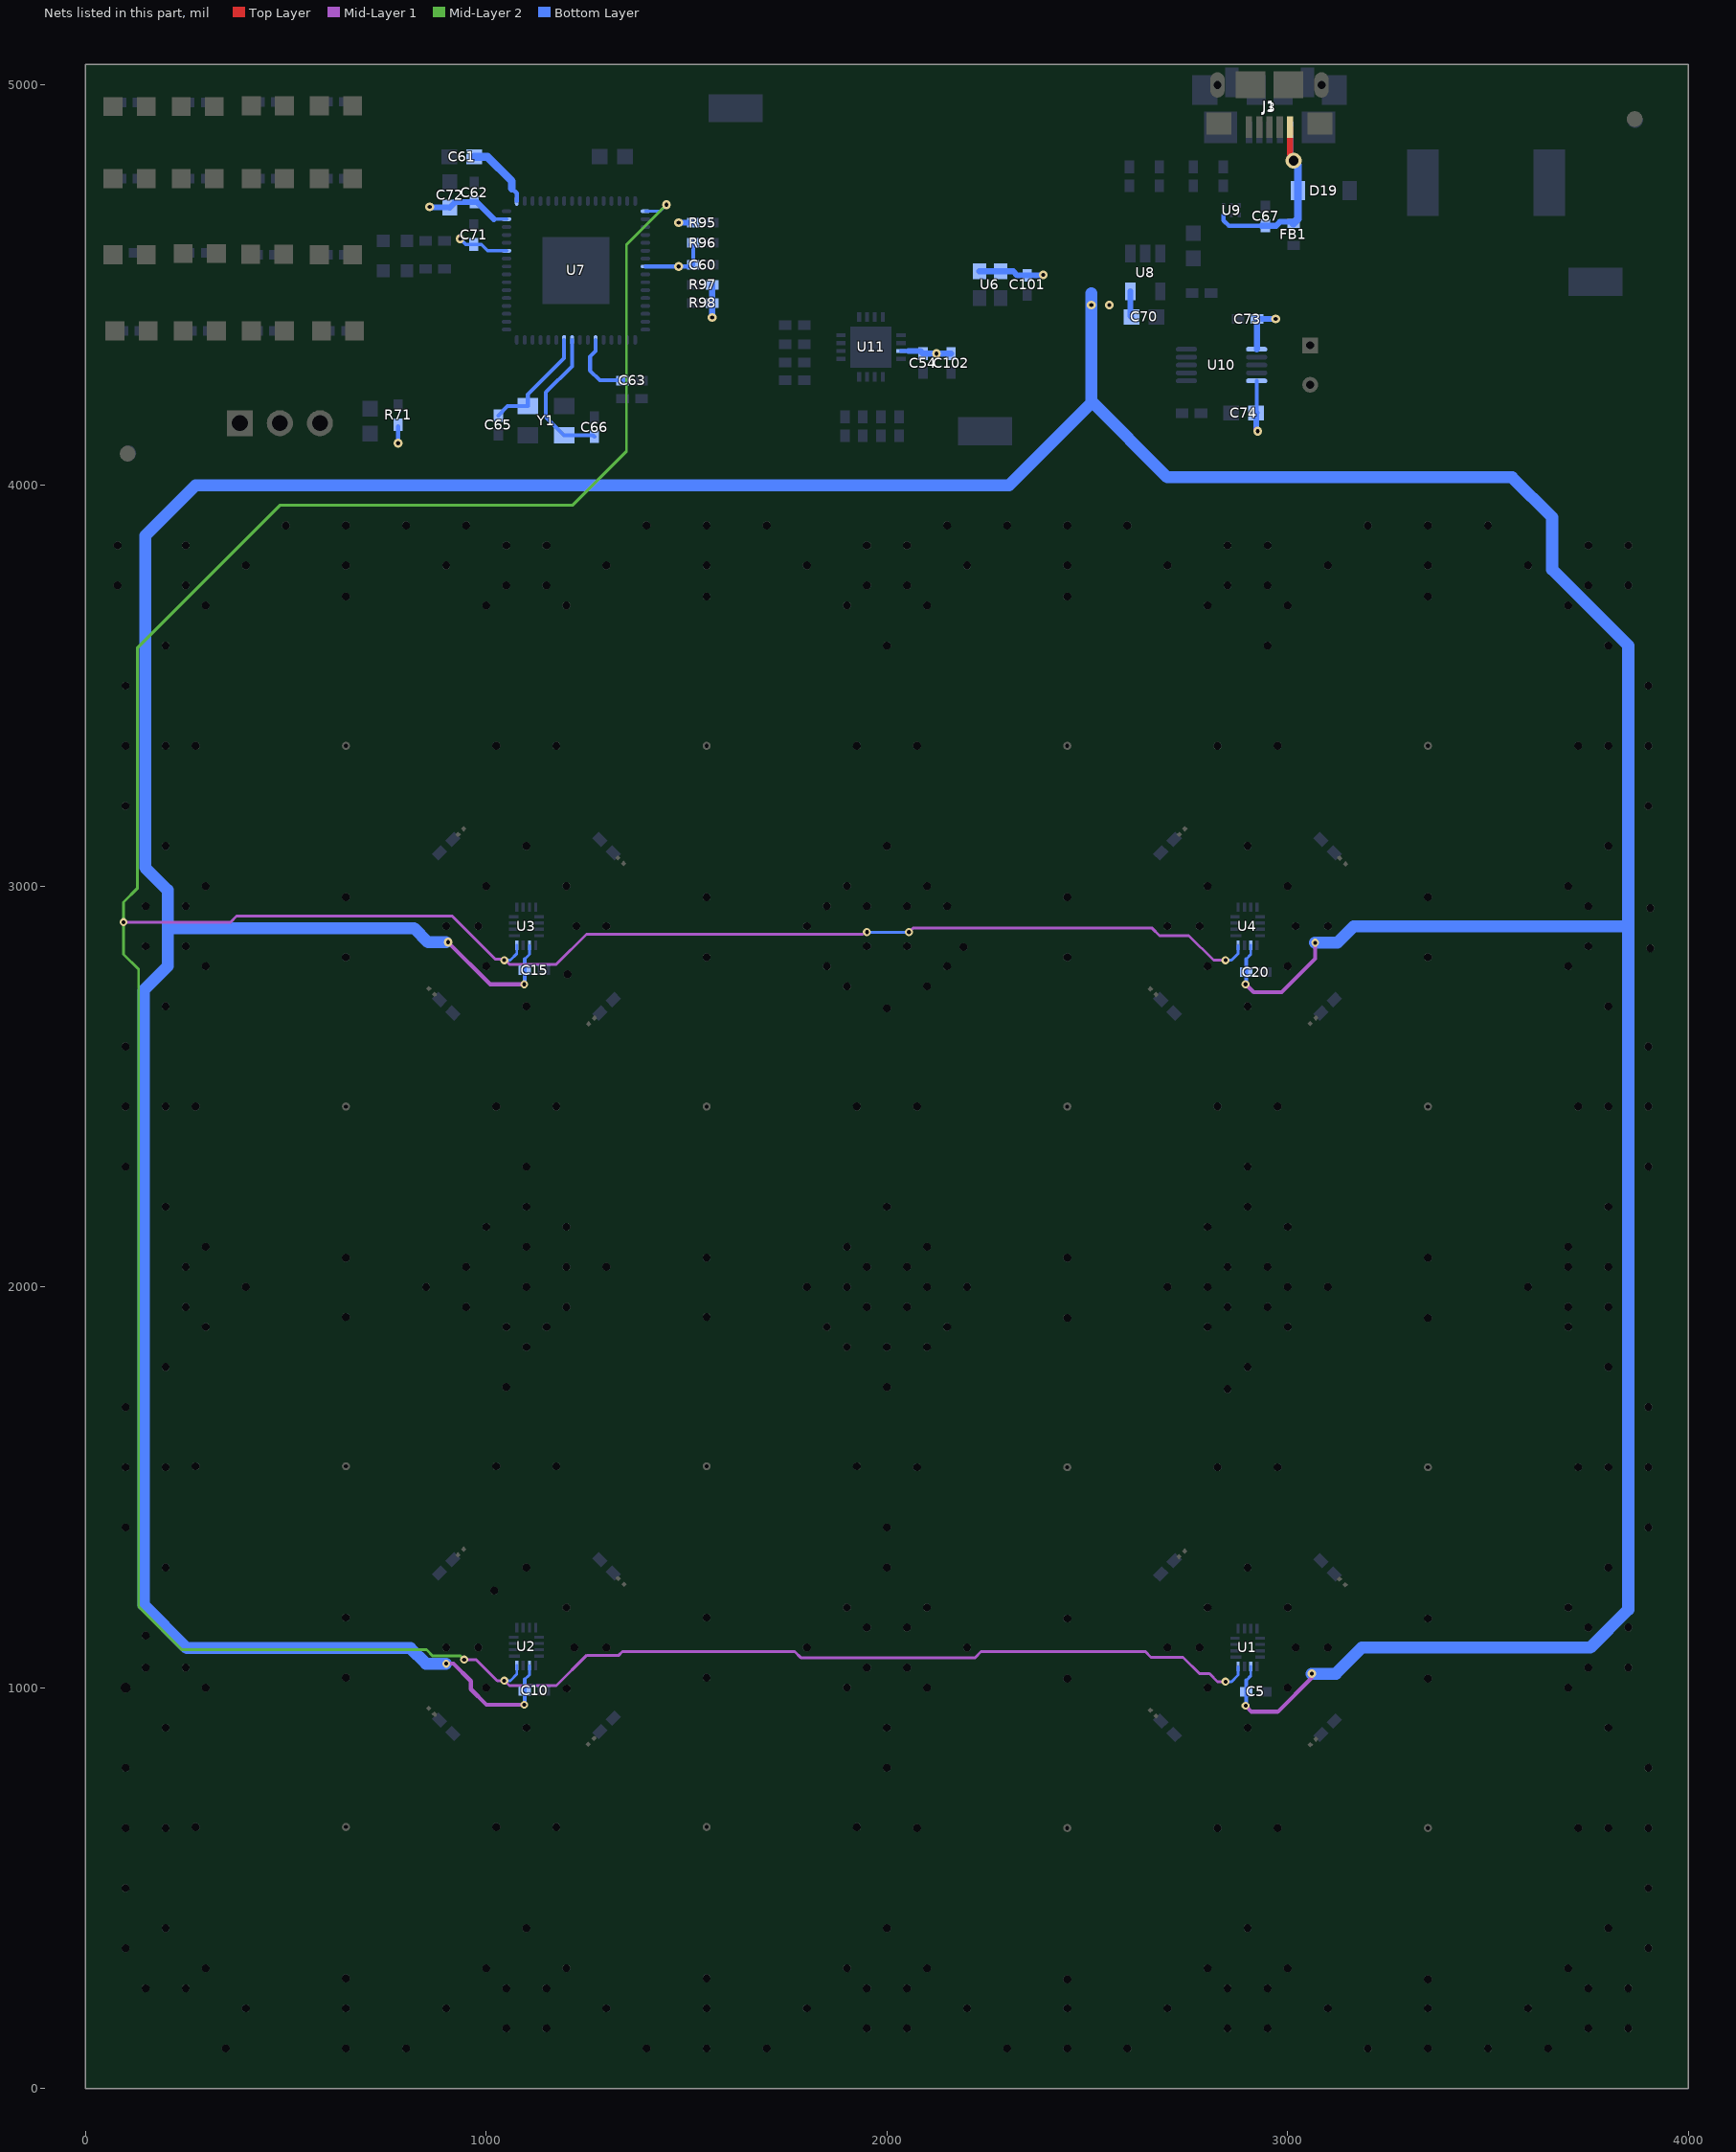
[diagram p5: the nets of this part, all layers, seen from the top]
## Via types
v1: diameter 22, hole 10, Top Layer to Bottom Layer, tented both sides, 185 vias
v2: diameter 20, hole 10, Top Layer to Bottom Layer, tented both sides, 80 vias
v3: diameter 19.68, hole 7.87, Top Layer to Bottom Layer, tented both sides, 5 vias
v4: diameter 40, hole 24, Top Layer to Bottom Layer, 4 vias
v5: diameter 40, hole 24, Top Layer to Bottom Layer, tented both sides, 1 vias

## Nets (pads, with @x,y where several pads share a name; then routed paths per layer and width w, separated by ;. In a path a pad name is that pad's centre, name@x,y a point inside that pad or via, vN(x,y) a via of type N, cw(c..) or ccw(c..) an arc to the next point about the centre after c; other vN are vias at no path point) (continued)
SS1: U1.16 U2.16 U3.16 U4.16 U7.33 | length 10536.9
  Mid-Layer 1 w7: v2(95,2910) 362,2910 377,2925 915,2925 1022.5,2817.5 1045,2817.5 1057.5,2805 1175,2805 1250,2880 1940,2880 ; v2(945,1070) 975,1070 1027.5,1017.5 v2(1045,1017.5) 1057.5,1005 1175,1005 1251,1081 1331,1081 1340,1090 1770,1090 1785,1075 2220,1075 2235,1090 2645,1090 2659,1076 2739,1076 2780,1035 2805,1035 2825,1015 v2(2845,1015) ; v2(2055,2885) 2065,2895 2662,2895 2680.5,2876.5 2753.5,2876.5 2815,2815 v2(2845,2815)
  Mid-Layer 2 w7: v2(945,1070) 936,1079 867,1079 851,1095 240,1095 132.53,1202.47 132.53,2792.47 95,2830 v2(95,2910) 95,2960 130,2995 130,3595 485,3950 1215,3950 1350,4085 1350,4600 v1(1450,4700)
  Bottom Layer w7: v2(1045,1017.5) 1060,1017.5 1076.38,1033.88 U2.16@1076.38,1055.26 ; v2(1045,2815) 1060,2815 1076.38,2831.38 U3.16@1076.38,2852.76 ; U7.33@1397.17,4683.7 1433.7,4683.7 v1(1450,4700) ; v2(1950,2885) v2(2055,2885) ; v2(2845,1015) 2860,1015 2876.38,1031.38 U1.16@2876.38,1052.76 ; v2(2845,2815) 2860,2815 2876.38,2831.38 U4.16@2876.38,2852.76
VBUS: C67.1 D19.1 FB1.1 J1.1 J3.1 U9.6 | length 512.3
  Top Layer w15: J1.1@3005.77,4893.6 3005.77,4824.84 3015.12,4815.48 v4(3015.12,4810)
  Bottom Layer w10: U9.6@2839.9,4674.19 2839.9,4660.68 2853.12,4647.47 C67.1@2934.5,4647.47
  Bottom Layer w15: C67.1@2934.5,4647.47 2971.06,4647.47 2981.09,4657.49 FB1.1@3014.59,4657.49 ; J3.1@3006.18,4870.49 3006.18,4827.46 v4@3019.38,4814.26
  Bottom Layer w20: FB1.1@3014.59,4653.56 3025.53,4664.5 D19.1@3025.53,4735 3025.53,4799.59 v4(3015.12,4810)
VCC: C5.1 C10.1 C15.1 C20.1 C54.1 C60.1 C62.1 C70.1 C71.1 C72.1 C73.2 C74.2 C101.1 C102.2 R71.1 R95.1 R96.1 R97.1 R98.1 U1.14 U2.14 U3.14 U4.14 U6.1 U6.4 U7.11 U7.15 U7.40 U8.5 U10.6 U10.10 U11.7 | length 15412.1
  Mid-Layer 1 w10: v2(900,1060) 918.35,1060 961.68,1016.68 961.68,996.32 1000.5,957.5 v2(1095,957.5) ; v1(905,2860) 1010,2755 v2(1095,2755) ; v2(2895,955) 2910,940 2975,940 3060,1025 v1(3060,1035) ; v2(2895,2755) 2915,2735 2985,2735 3068.62,2818.62 v2(3068.62,2858.62)
  Mid-Layer 1 w15: v1@2921.5,4138.5 v1(2925,4135)
  Bottom Layer w7: 1096.38,1020.53 1107.87,1032.03 U2.14@1107.87,1055.26 ; 1096.38,2818.03 1107.87,2829.53 U3.14@1107.87,2852.76 ; 2896.38,1018.03 2907.87,1029.53 U1.14@2907.87,1052.76 ; 2896.38,2818.03 2907.87,2829.53 U4.14@2907.87,2852.76
  Bottom Layer w9: v1(935,4615) 949.09,4600.91 C71.1@968.94,4600.91 988.06,4600.91 1003.69,4585.28 U7.11@1050.71,4585.28 ; 1019.11,4664.02 U7.15@1050.71,4664.02 ; U7.40@1397.17,4545.91 1414.09,4545.91
  Bottom Layer w10: v1(780,4105) R71.1@780,4146.69 ; v2(1095,957.5) 1096.38,958.88 1096.38,1020.53 ; v2(1095,2755) 1096.38,2756.38 1096.38,2818.03 ; U7.40@1397.17,4545.91 C60.1@1512.28,4545.91 ; C60.1@1516.38,4550 R96.1@1516.38,4605 ; U11.7@2034.8,4335.16 2053.27,4335.16 ; v2(2895,955) 2896.38,956.38 C5.1@2896.38,990 2896.38,1018.03 ; v2(2895,2755) 2896.38,2756.38 2896.38,2818.03 ; C74.2@2922.6,4181.1 U10.10@2922.6,4260.63
  Bottom Layer w15: v1(859.06,4695) 860.55,4693.5 C72.1@904.06,4693.5 ; C72.1@908.94,4693.03 922.28,4706.38 C62.1@970,4706.38 976.75,4706.38 1019.11,4664.02 ; v1(1480,4655) R95.1@1516.38,4655 ; R96.1@1512.38,4601 R96.1@1516.38,4605 ; v1(1563.62,4418.75) R98.1@1563.62,4455 R97.1@1563.62,4500 ; 2053.27,4335.16 2083.46,4335.16 C54.1@2090,4328.62 v1(2123.48,4328.62) C102.2@2160,4328.62 ; U6.4@2230.66,4533.93 U6.1@2283.81,4533.93 2315,4533.93 2325.3,4523.62 C101.1@2350,4523.62 2388.62,4523.62 v1(2390,4525) ; 2509.59,4479.5 2513.84,4483.75 ; U8.5@2607.19,4483.75 2607.19,4422.81 C70.1@2610,4420 ; v1@2921.5,4138.5 C74.2@2921.5,4180 C74.2@2922.6,4181.1 ; U10.6@2922.6,4339.37 2923.62,4340.39 C73.2@2923.62,4415 v1(2970,4415)
  Bottom Layer w30: v2(900,1060) 850,1060 811,1099 253,1099 145,1207 145,2740 205,2800 205,2900 ; v1@900,2860 855,2860 820,2895 210,2895 205,2900 ; 2509.59,4204.59 2305,4000 275,4000 149,3874 149,3046 205,2990 205,2900 ; 2509.59,4479.5 2509.59,4210.41 2700,4020 3560,4020 3660,3920 3660,3790 3850,3600 3850,2895 ; v1(3060,1035) 3120,1035 3185,1100 3755,1100 3850,1195 3850,2895 ; v2(3068.62,2858.62) 3123.62,2858.62 3165,2900 3845,2900 3850,2895
  other v1: 2510,4450 2555,4450 1480,4545.91
VCORE: C61.1 U7.17 | length 173.3
  Bottom Layer w10: 1063.94,4741.06 1076.26,4728.74 U7.17@1076.26,4709.29
  Bottom Layer w20: C61.1@970.43,4819.53 1003.23,4819.53 1063.94,4758.82 1063.94,4741.06
VUSB: C63.1 U7.54 | length 178.8
  Bottom Layer w10: U7.54@1273.16,4362.83 1273.16,4335.29 1258.94,4321.06 1258.94,4286.52 1283.52,4261.94 1345.19,4261.94 C63.1@1345.32,4262.06
XTALIN: C66.1 U7.57 Y1.1 | length 361.1
  Bottom Layer w10: U7.57@1214.09,4362.83 1214.09,4297.08 1148.94,4231.93 1148.94,4169.92 Y1.1@1194.21,4124.65 1266.73,4124.65 C66.1@1270,4121.38
XTALOUT: C65.1 U7.58 Y1.3 | length 286.3
  Bottom Layer w10: C65.1@1030,4174.06 1053.42,4197.48 Y1.3@1103.66,4197.48 1103.66,4226.65 1194.4,4317.39 U7.58@1194.4,4362.83
pads on no net: FID1.1 FID2.1 FID3.1 FID4.1 J1.4 J3.4 LBL1.0 U7.12 U7.13 U7.26 U7.28 U7.36 U7.37 U7.38 U7.41 U7.45 U7.46 U7.47 U7.48 U7.60 U7.61 U7.62 U7.63 U9.4 U9.5

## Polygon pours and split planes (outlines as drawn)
GND on Bottom Layer "Bottom Layer-No Net" (solid, remove dead copper, pour order 14): 1098.94,4656.06 1098.94,4431.06 1098.94,4411.45 1343.55,4411.45 1348.94,4406.06 1348.94,4656.06 1098.94,4656.06
GND on Bottom Layer "Bottom Layer-No Net 1" (solid, remove dead copper, pour order 12): 2110,4420 2200,4420 2200,4360 2210,4350 2350,4350 2350,4130 2310,4090 2190,4090 1880,4090 1710,4090 1645,4090 1645,4305 1650,4310 1766.22,4310 1766.22,4243.78 1770,4240 1880,4130 1883.19,4130 2050,4130 2090,4170 2090,4290 2150,4290 2150,4325 2145,4325 2100,4370 2100,4420
GND on Bottom Layer "Top Layer-No Net" (solid, remove dead copper, pour order 11): 25,4050 3975,4050 3975,25 25,25 25,4050
GND on Bottom Layer "Top Layer-No Net" (solid, remove dead copper, pour order 16): 1295,4290 1670,4290 1675,4295 1750,4220 2350,4220 2350,3930 1750,3925 40,3925 35,3930 25,3940 25,4235 1240,4235
VCC on Mid-Layer 2 "Top Layer-No Net" (solid, remove dead copper, pour order 9): 25,5025 3975,5025 3975,4075 2325,4075 25,4075 25,5025
GND on Mid-Layer 2 "Top Layer-No Net" (solid, remove dead copper, pour order 13): 25,4050 3975,4050 3975,25 25,25 25,4050
GND on Top Layer "Top Layer-No Net" (solid, remove dead copper, pour order 10): 25,5025 3975,5025 3975,25 25,25 25,5025
GND on Mid-Layer 1 "Top Layer-No Net" (solid, remove dead copper, pour order 15): 25,5025 3975,5025 3975,25 25,25 25,5025
no net on Top Solder "NONET_L-01_P-001" (solid): 0,4000 4000,4000 4000,0 0,0

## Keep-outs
Keep-Out Layer:
  lines w1: 0.01,3999.99 0.01,-0.01 4000.01,-0.01 4000.01,3999.99
  lines w10: 0.01,3999.99 0.01,-0.01 4000.01,-0.01 4000.01,94.99 4000.01,3999.99
  lines w15: -7.5,0 ccw(c0,0) 0,-7.5 ; -7.5,0 ccw(c0,0) 0,-7.5 ; -7.5,0 -7.5,5050 ; -7.5,5050 cw(c0,5050) 0,5057.5 ; -7.5,5050 cw(c0,5050) 0,5057.5 ; 0,-7.5 4000,-7.5 ; 0,5057.5 4000,5057.5 ; 4000,-7.5 ccw(c4000,0) 4007.5,0 ; 4000,-7.5 ccw(c4000,0) 4007.5,0 ; 4000,5057.5 cw(c4000,5050) 4007.5,5050 ; 4000,5057.5 cw(c4000,5050) 4007.5,5050 ; 4007.5,0 4007.5,5050
  text ".Layer_Name" at 577,-858.49 h60

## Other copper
Top Layer:
  rectangle net GND: 2670,4920 2755,4980
  rectangle net GND: 3049.59,4871 3159.59,5031
  rectangle net GND: 2780,4950 3135,5025
  rectangle net GND: 2745,4865 2830,5025
  pour cut-out: 1040,4230 1240,4230 1240,4100 1040,4100
  pour cut-out: 600,2975 700,2975 700,2825 600,2825
  pour cut-out: 600,2075 700,2075 700,1925 600,1925
  pour cut-out: 600,1175 700,1175 700,1025 600,1025
  pour cut-out: 1500,1175 1600,1175 1600,1025 1500,1025
  pour cut-out: 1500,2975 1600,2975 1600,2825 1500,2825
  pour cut-out: 2400,2975 2500,2975 2500,2825 2400,2825
  pour cut-out: 3300,2975 3400,2975 3400,2825 3300,2825
  pour cut-out: 3300,2075 3400,2075 3400,1925 3300,1925
  pour cut-out: 2400,1175 2500,1175 2500,1025 2400,1025
  pour cut-out: 3300,1175 3400,1175 3400,1025 3300,1025
  pour cut-out: 652.53,246.02 cw(c650.02,653.51) 242.52,653.51 cw(c650.02,653.51) 650.02,1061.01 cw(c650.02,653.51) 1057.51,651 cw(c652.53,651)
  pour cut-out: 1552.54,246.04 cw(c1550.03,653.54) 1142.53,653.54 cw(c1550.03,653.54) 1550.03,1061.04 cw(c1550.03,653.54) 1957.52,651.03 cw(c1552.54,651.03)
  pour cut-out: 2452.52,243.53 cw(c2450.01,651.03) 2042.51,651.03 cw(c2450.01,651.03) 2450.01,1058.53 cw(c2450.01,651.03) 2857.5,648.52 cw(c2452.52,648.52)
  pour cut-out: 3352.54,243.54 cw(c3350.03,651.04) 2942.53,651.04 cw(c3350.03,651.04) 3350.03,1058.54 cw(c3350.03,651.04) 3757.52,648.53 cw(c3352.54,648.53)
  pour cut-out: 3352.52,1143.53 cw(c3350.01,1551.03) 2942.51,1551.03 cw(c3350.01,1551.03) 3350.01,1958.53 cw(c3350.01,1551.03) 3757.5,1548.52 cw(c3352.52,1548.52)
  pour cut-out: 2452.52,1143.53 cw(c2450.01,1551.03) 2042.51,1551.03 cw(c2450.01,1551.03) 2450.01,1958.53 cw(c2450.01,1551.03) 2857.5,1548.52 cw(c2452.52,1548.52)
  pour cut-out: 1552.52,1146.03 cw(c1550.01,1553.53) 1142.51,1553.53 cw(c1550.01,1553.53) 1550.01,1961.03 cw(c1550.01,1553.53) 1957.5,1551.02 cw(c1552.52,1551.02)
  pour cut-out: 652.52,1146.03 cw(c650.01,1553.53) 242.51,1553.53 cw(c650.01,1553.53) 650.01,1961.03 cw(c650.01,1553.53) 1057.5,1551.02 cw(c652.52,1551.02)
  pour cut-out: 3352.54,2043.54 cw(c3350.03,2451.04) 2942.53,2451.04 cw(c3350.03,2451.04) 3350.03,2858.54 cw(c3350.03,2451.04) 3757.52,2448.53 cw(c3352.54,2448.53)
  pour cut-out: 2452.52,2043.53 cw(c2450.01,2451.03) 2042.51,2451.03 cw(c2450.01,2451.03) 2450.01,2858.53 cw(c2450.01,2451.03) 2857.5,2448.52 cw(c2452.52,2448.52)
  pour cut-out: 1552.52,2043.53 cw(c1550.01,2451.03) 1142.51,2451.03 cw(c1550.01,2451.03) 1550.01,2858.53 cw(c1550.01,2451.03) 1957.5,2448.52 cw(c1552.52,2448.52)
  pour cut-out: 652.53,2043.51 cw(c650.02,2451.01) 242.52,2451.01 cw(c650.02,2451.01) 650.02,2858.51 cw(c650.02,2451.01) 1057.51,2448.5 cw(c652.53,2448.5)
  pour cut-out: 3352.52,2943.53 cw(c3350.01,3351.03) 2942.51,3351.03 cw(c3350.01,3351.03) 3350.01,3758.53 cw(c3350.01,3351.03) 3757.5,3348.52 cw(c3352.52,3348.52)
  pour cut-out: 2452.52,2943.53 cw(c2450.01,3351.03) 2042.51,3351.03 cw(c2450.01,3351.03) 2450.01,3758.53 cw(c2450.01,3351.03) 2857.5,3348.52 cw(c2452.52,3348.52)
  pour cut-out: 1552.52,2943.53 cw(c1550.01,3351.03) 1142.51,3351.03 cw(c1550.01,3351.03) 1550.01,3758.53 cw(c1550.01,3351.03) 1957.5,3348.52 cw(c1552.52,3348.52)
  pour cut-out: 652.51,2943.51 cw(c650,3351) 242.5,3351 cw(c650,3351) 650,3758.5 cw(c650,3351) 1057.49,3348.49 cw(c652.51,3348.49)
  text ".Layer_Name" at 577,-858.49 h60
Mid-Layer 1:
  rectangle net GND: 1900,4288.86 1986,4405
  pour cut-out: 1040,4230 1240,4230 1240,4100 1040,4100
  pour cut-out: 600,2975 700,2975 700,2825 600,2825
  pour cut-out: 1500,2975 1600,2975 1600,2825 1500,2825
  pour cut-out: 2400,2975 2500,2975 2500,2825 2400,2825
  pour cut-out: 3300,2975 3400,2975 3400,2825 3300,2825
  pour cut-out: 600,2075 700,2075 700,1925 675,1950 600,1950
  pour cut-out: 3300,2075 3400,2075 3400,1925 3300,1925
  pour cut-out: 3300,1175 3400,1175 3400,1025 3300,1025
  pour cut-out: 2400,1175 2500,1175 2500,1025 2400,1025
  pour cut-out: 1500,1175 1600,1175 1600,1025 1500,1025
  pour cut-out: 600,1175 700,1175 700,1025 600,1025
  pour cut-out: 649.53,2942.52 cw(c649.53,3350.02) 242.03,3350.02 cw(c649.53,3350.02) 649.53,3757.52 cw(c649.53,3350.02) 1057.03,3350.02 1057.02,3350.02 cw(c649.53,3350.01)
  pour cut-out: 3349.51,242.51 cw(c3349.51,650.01) 2942.01,650.01 cw(c3349.51,650.01) 3349.51,1057.51 cw(c3349.51,650.01) 3757.01,650.01 3757,650.01 cw(c3349.51,650.01)
  pour cut-out: 2449.51,242.51 cw(c2449.51,650.01) 2042.01,650.01 cw(c2449.51,650.01) 2449.51,1057.51 cw(c2449.51,650.01) 2857.01,650.01 2857,650.01 cw(c2449.51,650.01)
  pour cut-out: 1549.51,245.01 cw(c1549.51,652.51) 1142.01,652.51 cw(c1549.51,652.51) 1549.51,1060.01 cw(c1549.51,652.51) 1957.01,652.51 1957,652.51 cw(c1549.51,652.51)
  pour cut-out: 649.51,245.01 cw(c649.51,652.51) 242.01,652.51 cw(c649.51,652.51) 649.51,1060.01 cw(c649.51,652.51) 1057.01,652.51 1057,652.51 cw(c649.51,652.51)
  pour cut-out: 3349.53,1142.5 cw(c3349.53,1550) 2942.03,1550 cw(c3349.53,1550) 3349.53,1957.51 cw(c3349.53,1550) 3757.03,1550 3757.02,1550 cw(c3349.53,1550)
  pour cut-out: 2449.52,1142.53 cw(c2449.52,1550.03) 2042.02,1550.03 cw(c2449.52,1550.03) 2449.52,1957.53 cw(c2449.52,1550.03) 2857.02,1550.03 2857.01,1550.03 cw(c2449.51,1550.03)
  pour cut-out: 1549.53,1145 cw(c1549.53,1552.5) 1142.03,1552.5 cw(c1549.53,1552.5) 1549.53,1960.01 cw(c1549.53,1552.5) 1957.03,1552.5 1957.02,1552.5 cw(c1549.53,1552.5)
  pour cut-out: 649.52,1145.03 cw(c649.52,1552.53) 242.02,1552.53 cw(c649.52,1552.53) 649.52,1960.03 cw(c649.52,1552.53) 1057.02,1552.53 1057.01,1552.53 cw(c649.51,1552.53)
  pour cut-out: 3349.51,2042.51 cw(c3349.51,2450.01) 2942.01,2450.01 cw(c3349.51,2450.01) 3349.51,2857.51 cw(c3349.51,2450.01) 3757.01,2450.01 3757,2450.01 cw(c3349.51,2450.01)
  pour cut-out: 2449.49,2042.52 cw(c2449.49,2450.02) 2041.99,2450.02 cw(c2449.49,2450.02) 2449.49,2857.52 cw(c2449.49,2450.02) 2856.99,2450.02 2856.98,2450.02 cw(c2449.49,2450.01)
  pour cut-out: 1549.51,2042.51 cw(c1549.51,2450.01) 1142.01,2450.01 cw(c1549.51,2450.01) 1549.51,2857.51 cw(c1549.51,2450.01) 1957.01,2450.01 1957,2450.01 cw(c1549.51,2450.01)
  pour cut-out: 649.51,2042.51 cw(c649.51,2450.01) 242.01,2450.01 cw(c649.51,2450.01) 649.51,2857.51 cw(c649.51,2450.01) 1057.01,2450.01 1057,2450.01 cw(c649.51,2450.01)
  pour cut-out: 3349.99,2942.48 cw(c3349.99,3349.98) 2942.49,3349.98 cw(c3349.99,3349.98) 3349.99,3757.48 cw(c3349.99,3349.98) 3757.49,3349.98 3757.47,3349.98 cw(c3349.98,3349.98)
  pour cut-out: 2449.51,2942.51 cw(c2449.51,3350.01) 2042.01,3350.01 cw(c2449.51,3350.01) 2449.51,3757.51 cw(c2449.51,3350.01) 2857.01,3350.01 2857,3350.01 cw(c2449.51,3350.01)
  pour cut-out: 1549.53,2942.5 cw(c1549.53,3350.01) 1142.03,3350.01 cw(c1549.53,3350.01) 1549.53,3757.51 cw(c1549.53,3350.01) 1957.03,3350.01 1957.02,3350.01 cw(c1549.53,3350)
  text ".Layer_Name" at 580,-855 h60
Mid-Layer 2:
  pour cut-out: 1040,4230 1240,4230 1240,4100 1040,4100
  pour cut-out: 600,1175 700,1175 700,1025 600,1025
  pour cut-out: 1500,1175 1600,1175 1600,1025 1500,1025
  pour cut-out: 2400,1175 2500,1175 2500,1025 2400,1025
  pour cut-out: 3300,1175 3400,1175 3400,1025 3300,1025
  pour cut-out: 3300,2075 3400,2075 3400,1925 3300,1925
  pour cut-out: 3300,3000 3400,3000 3400,2825 3300,2825
  pour cut-out: 2400,2975 2500,2975 2500,2825 2400,2825
  pour cut-out: 600,2075 700,2075 700,1925 600,1925
  pour cut-out: 600,2975 700,2975 700,2825 600,2825
  pour cut-out: 1500,2975 1600,2975 1600,2825 1500,2825
  pour cut-out: 3349.51,242.96 cw(c3349.51,650.46) 2942.01,650.46 cw(c3349.51,650.46) 3349.51,1057.96 cw(c3349.51,650.46) 3757.02,650.46 3757,650.46 cw(c3349.51,650.45)
  pour cut-out: 2449.51,242.96 cw(c2449.51,650.46) 2042.01,650.46 cw(c2449.51,650.46) 2449.51,1057.96 cw(c2449.51,650.46) 2857.02,650.46 2857,650.46 cw(c2449.51,650.45)
  pour cut-out: 1549.51,245.46 cw(c1549.51,652.96) 1142.01,652.96 cw(c1549.51,652.96) 1549.51,1060.46 cw(c1549.51,652.96) 1957.02,652.96 1957,652.96 cw(c1549.51,652.95)
  pour cut-out: 649.51,245.46 cw(c649.51,652.96) 242.01,652.96 cw(c649.51,652.96) 649.51,1060.46 cw(c649.51,652.96) 1057.02,652.96 1057,652.96 cw(c649.51,652.95)
  pour cut-out: 3349.51,1142.96 cw(c3349.51,1550.46) 2942.01,1550.46 cw(c3349.51,1550.46) 3349.51,1957.96 cw(c3349.51,1550.46) 3757.02,1550.46 3757,1550.46 cw(c3349.51,1550.45)
  pour cut-out: 2449.51,1142.96 cw(c2449.51,1550.46) 2042.01,1550.46 cw(c2449.51,1550.46) 2449.51,1957.96 cw(c2449.51,1550.46) 2857.02,1550.46 2857,1550.46 cw(c2449.51,1550.45)
  pour cut-out: 1549.51,1145.46 cw(c1549.51,1552.96) 1142.01,1552.96 cw(c1549.51,1552.96) 1549.51,1960.46 cw(c1549.51,1552.96) 1957.02,1552.96 1957,1552.96 cw(c1549.51,1552.95)
  pour cut-out: 649.51,1145.46 cw(c649.51,1552.96) 242.01,1552.96 cw(c649.51,1552.96) 649.51,1960.46 cw(c649.51,1552.96) 1057.02,1552.96 1057,1552.96 cw(c649.51,1552.95)
  pour cut-out: 3349.51,2042.96 cw(c3349.51,2450.46) 2942.01,2450.46 cw(c3349.51,2450.46) 3349.51,2857.96 cw(c3349.51,2450.46) 3757.02,2450.46 3757,2450.46 cw(c3349.51,2450.45)
  pour cut-out: 2449.51,2042.96 cw(c2449.51,2450.46) 2042.01,2450.46 cw(c2449.51,2450.46) 2449.51,2857.96 cw(c2449.51,2450.46) 2857.02,2450.46 2857,2450.46 cw(c2449.51,2450.45)
  pour cut-out: 1549.51,2042.96 cw(c1549.51,2450.46) 1142.01,2450.46 cw(c1549.51,2450.46) 1549.51,2857.96 cw(c1549.51,2450.46) 1957.02,2450.46 1957,2450.46 cw(c1549.51,2450.45)
  pour cut-out: 649.51,2042.96 cw(c649.51,2450.46) 242.01,2450.46 cw(c649.51,2450.46) 649.51,2857.96 cw(c649.51,2450.46) 1057.02,2450.46 1057,2450.46 cw(c649.51,2450.45)
  pour cut-out: 3349.51,2942.96 cw(c3349.51,3350.46) 2942.01,3350.46 cw(c3349.51,3350.46) 3349.51,3757.96 cw(c3349.51,3350.46) 3757.02,3350.46 3757,3350.46 cw(c3349.51,3350.45)
  pour cut-out: 2449.51,2942.96 cw(c2449.51,3350.46) 2042.01,3350.46 cw(c2449.51,3350.46) 2449.51,3757.96 cw(c2449.51,3350.46) 2857.02,3350.46 2857,3350.46 cw(c2449.51,3350.45)
  pour cut-out: 1549.51,2942.96 cw(c1549.51,3350.46) 1142.01,3350.46 cw(c1549.51,3350.46) 1549.51,3757.96 cw(c1549.51,3350.46) 1957.02,3350.46 1957,3350.46 cw(c1549.51,3350.45)
  pour cut-out: 649.51,2942.96 cw(c649.51,3350.46) 242.01,3350.46 cw(c649.51,3350.46) 649.51,3757.96 cw(c649.51,3350.46) 1057.02,3350.46 1057,3350.46 cw(c649.51,3350.45)
  text ".Layer_Name" at 580,-860 h60
Bottom Layer:
  rectangle net GND: 2685,4920 2777.1,4980.22
  rectangle net GND: 2855,4855.21 2910,4905
  rectangle net VCC: 2495,4400 2615,4500
  rectangle net GND: 3045,4835 3180,5035
  rectangle net GND: 2760,4835 2870,5035
  rectangle net GND: 2855,4940 3077.69,5024.99
  pour cut-out: 600,1175 700,1175 700,1025 600,1025
  pour cut-out: 1500,1175 1600,1175 1600,1025 1500,1025
  pour cut-out: 2400,1175 2500,1175 2500,1025 2400,1025
  pour cut-out: 3300,1175 3400,1175 3400,1025 3300,1025
  pour cut-out: 3300,2075 3400,2075 3400,1925 3300,1925
  pour cut-out: 600,2075 700,2075 700,1925 600,1925
  pour cut-out: 600,2975 700,2975 700,2825 600,2825
  pour cut-out: 1500,2975 1600,2975 1600,2825 1500,2825
  pour cut-out: 2400,2975 2500,2975 2500,2825 2400,2825
  pour cut-out: 3300,2975 3400,2975 3400,2825 3300,2825
  pour cut-out: 3350.02,242.54 cw(c3350.02,650.04) 2942.52,650.04 cw(c3350.02,650.04) 3350.02,1057.54 cw(c3350.02,650.04) 3757.53,650.04 3757.51,650.04 cw(c3350.02,650.03)
  pour cut-out: 2450.02,242.54 cw(c2450.02,650.04) 2042.52,650.04 cw(c2450.02,650.04) 2450.02,1057.54 cw(c2450.02,650.04) 2857.53,650.04 2857.51,650.04 cw(c2450.02,650.03)
  pour cut-out: 1550.02,245.04 cw(c1550.02,652.54) 1142.52,652.54 cw(c1550.02,652.54) 1550.02,1060.04 cw(c1550.02,652.54) 1957.53,652.54 1957.51,652.54 cw(c1550.02,652.53)
  pour cut-out: 653.02,246.04 cw(c653.02,653.54) 245.52,653.54 cw(c651.51,655.04) 650.02,1061.03 cw(c651.53,652.03) 1060.53,653.54 cw(c653.03,653.54)
  pour cut-out: 3350.02,1142.54 cw(c3350.02,1550.04) 2942.52,1550.04 cw(c3350.02,1550.04) 3350.02,1957.54 cw(c3350.02,1550.04) 3757.53,1550.04 3757.51,1550.04 cw(c3350.02,1550.03)
  pour cut-out: 2450.02,1142.54 cw(c2450.02,1550.04) 2042.52,1550.04 cw(c2450.02,1550.04) 2450.02,1957.54 cw(c2450.02,1550.04) 2857.53,1550.04 2857.51,1550.04 cw(c2450.02,1550.03)
  pour cut-out: 1550.02,1145.04 cw(c1550.02,1552.54) 1142.52,1552.54 cw(c1550.02,1552.54) 1550.02,1960.04 cw(c1550.02,1552.54) 1957.53,1552.54 1957.51,1552.54 cw(c1550.02,1552.53)
  pour cut-out: 650.02,1145.04 cw(c650.02,1552.54) 242.52,1552.54 cw(c650.02,1552.54) 650.02,1960.04 cw(c650.02,1552.54) 1057.53,1552.54 1057.51,1552.54 cw(c650.02,1552.53)
  pour cut-out: 3350.02,2042.54 cw(c3350.02,2450.04) 2942.52,2450.04 cw(c3350.02,2450.04) 3350.02,2857.54 cw(c3350.02,2450.04) 3757.53,2450.04 3757.51,2450.04 cw(c3350.02,2450.03)
  pour cut-out: 2450.02,2042.54 cw(c2450.02,2450.04) 2042.52,2450.04 cw(c2450.02,2450.04) 2450.02,2857.54 cw(c2450.02,2450.04) 2857.53,2450.04 2857.51,2450.04 cw(c2450.02,2450.03)
  pour cut-out: 1550.02,2042.54 cw(c1550.02,2450.04) 1142.52,2450.04 cw(c1550.02,2450.04) 1550.02,2857.54 cw(c1550.02,2450.04) 1957.53,2450.04 1957.51,2450.04 cw(c1550.02,2450.03)
  pour cut-out: 650.02,2042.54 cw(c650.02,2450.04) 242.52,2450.04 cw(c650.02,2450.04) 650.02,2857.54 cw(c650.02,2450.04) 1057.53,2450.04 1057.51,2450.04 cw(c650.02,2450.03)
  pour cut-out: 3350.02,2942.54 cw(c3350.02,3350.04) 2942.52,3350.04 cw(c3350.02,3350.04) 3350.02,3757.54 cw(c3350.02,3350.04) 3757.53,3350.04 3757.51,3350.04 cw(c3350.02,3350.03)
  pour cut-out: 2450.02,2942.54 cw(c2450.02,3350.04) 2042.52,3350.04 cw(c2450.02,3350.04) 2450.02,3757.54 cw(c2450.02,3350.04) 2857.53,3350.04 2857.51,3350.04 cw(c2450.02,3350.03)
  pour cut-out: 1550.02,2942.54 cw(c1550.02,3350.04) 1142.52,3350.04 cw(c1550.02,3350.04) 1550.02,3757.54 cw(c1550.02,3350.04) 1957.53,3350.04 1957.51,3350.04 cw(c1550.02,3350.03)
  pour cut-out: 650.01,2942.51 cw(c650.01,3350.01) 242.51,3350.01 cw(c650.01,3350.01) 650.01,3757.51 cw(c650.01,3350.01) 1057.51,3350.01 1057.5,3350.01 cw(c650.01,3350.01)
  text ".Layer_Name" at 577,-858.49 h60

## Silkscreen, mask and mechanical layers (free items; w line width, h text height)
Top Overlay:
  rectangle: 3535,4370 3885,4470
  lines w10: 15,3990 3975,3990
  text "Touch on Metal" at 1155,4835 h200
  text "16 BUTTON" at 1550,4685 h75
  text "TIDA-01102" at 3095,4405 h50
  text "REV A" at 3620,4295 h50
  text ".Layer_Name" at 577,-858.49 h30
Bottom Overlay:
  lines w10: 2053.27,4232.37 2102.37,4232.37 2124.86,4254.86 2124.86,4545.14 2110,4560 1850,4560 ; 2061.69,4560 1850,4560 ; 2062.39,4232.37 1852.26,4232.37 1832.59,4252.04 1832.59,4545.46 1847.13,4560 1850,4560 ; 2124.86,4370.14 2124.86,4473.45
  text "GND" at 1846.92,4922.54 h40
  text "LDC1614" at 2045,4510 h30
  text "GND" at 3825,4391 h40
  text "GND" at 2440,4105 h40
  text "RST" at 425,4050 h40
  text "GND" at 635,4045 h40
  text ".Layer_Name" at 577,-858.49 h30
Top Paste:
  text ".Layer_Name" at 577,-858.49 h60
Bottom Paste:
  text ".Layer_Name" at 577,-858.49 h60
Top Solder:
  pour cut-out: 650,1158.8 cw(c650,1552.5) 256.3,1552.5 cw(c650,1552.5) 650,1946.2 cw(c650,1552.5) 1043.7,1552.5 cw(c650,1552.5)
  pour cut-out: 1550,1158.8 cw(c1550,1552.5) 1156.3,1552.5 cw(c1550,1552.5) 1550,1946.2 cw(c1550,1552.5) 1943.7,1552.5 cw(c1550,1552.5)
  pour cut-out: 2450,1158.8 cw(c2450,1552.5) 2056.3,1552.5 cw(c2450,1552.5) 2450,1946.2 cw(c2450,1552.5) 2843.7,1552.5 cw(c2450,1552.5)
  pour cut-out: 3350,1158.8 cw(c3350,1552.5) 2956.3,1552.5 cw(c3350,1552.5) 3350,1946.2 cw(c3350,1552.5) 3743.7,1552.5 cw(c3350,1552.5)
  pour cut-out: 3350,258.8 cw(c3350,652.5) 2956.3,652.5 cw(c3350,652.5) 3350,1046.2 cw(c3350,652.5) 3743.7,652.5 cw(c3350,652.5)
  pour cut-out: 2450,258.8 cw(c2450,652.5) 2056.3,652.5 cw(c2450,652.5) 2450,1046.2 cw(c2450,652.5) 2843.7,652.5 cw(c2450,652.5)
  pour cut-out: 1550,258.8 cw(c1550,652.5) 1156.3,652.5 cw(c1550,652.5) 1550,1046.2 cw(c1550,652.5) 1943.7,652.5 cw(c1550,652.5)
  pour cut-out: 650,258.8 cw(c650,652.5) 256.3,652.5 cw(c650,652.5) 650,1046.2 cw(c650,652.5) 1043.7,652.5 cw(c650,652.5)
  pour cut-out: 650,2056.3 cw(c650,2450) 256.3,2450 cw(c650,2450) 650,2843.7 cw(c650,2450) 1043.7,2450 cw(c650,2450)
  pour cut-out: 1550,2056.3 cw(c1550,2450) 1156.3,2450 cw(c1550,2450) 1550,2843.7 cw(c1550,2450) 1943.7,2450 cw(c1550,2450)
  pour cut-out: 2450,2056.3 cw(c2450,2450) 2056.3,2450 cw(c2450,2450) 2450,2843.7 cw(c2450,2450) 2843.7,2450 cw(c2450,2450)
  pour cut-out: 3350,2056.3 cw(c3350,2450) 2956.3,2450 cw(c3350,2450) 3350,2843.7 cw(c3350,2450) 3743.7,2450 cw(c3350,2450)
  pour cut-out: 3350,2956.3 cw(c3350,3350) 2956.3,3350 cw(c3350,3350) 3350,3743.7 cw(c3350,3350) 3743.7,3350 cw(c3350,3350)
  pour cut-out: 2450,2956.3 cw(c2450,3350) 2056.3,3350 cw(c2450,3350) 2450,3743.7 cw(c2450,3350) 2843.7,3350 cw(c2450,3350)
  pour cut-out: 1550,2956.3 cw(c1550,3350) 1156.3,3350 cw(c1550,3350) 1550,3743.7 cw(c1550,3350) 1943.7,3350 cw(c1550,3350)
  pour cut-out: 650,2956.3 cw(c650,3350) 256.3,3350 cw(c650,3350) 650,3743.7 cw(c650,3350) 1043.7,3350 cw(c650,3350)
  text ".Layer_Name" at 577,-858.49 h60
  text ".Layer_Name" at 577,-858.49 h60
Bottom Solder:
  text ".Layer_Name" at 577,-858.49 h60
Drill Guide:
  text ".Layer_Name" at 577,-858.49 h60
M1 Board Outline:
  lines w10: 4000,4050 4000,5050 ; 0,0 0,5050 ; 0,0 0,5050 ; 0.01,0 4000,0 4000,5050 ; 0,5050 3000,5050 4000,5050 ; 0,5050 4000,5050 ; 4000,5050 4000,5050 ; 2967.16,5049.41 2967.16,5049.41
  lines w15: 4000,0 4000,5050
  text ".Layer_Name" at 577,-858.49 h60
M2 Board Dimensions:
  rectangle: 125,-400 500,-275
  rectangle: 0,-275 125,-150
  lines w7: 0,-275 1000,-275 ; 0,-150 0,-400 1000,-400 1000,-150 ; 125,-400 125,-150 ; 250,-400 250,-150 ; 500,-400 500,-150 ; 750,-400 750,-150
  text ".Layer_Name" at 577,-858.49 h60
M3 3D STEP Top:
  text ".Layer_Name" at 577,-858.49 h60
M4 3D STEP Bottom:
  text ".Layer_Name" at 577,-858.49 h60
M5 Assembly Top:
  lines w10: -292,-930.17 6308,-930.17 ; -292,-726.83 6310,-726.83 ; -292,-523.5 -292,-1133.5 3713,-1133.5 6310,-1133.5 6310,-523.5 -291.5,-523.5 -291.5,-1133.5 1284,-1133.5 ; 2173,-1133.5 2173,-523.5 ; 3440,-726.83 3440,-523.5 ; 4280,-726.83 4280,-523.5 ; 4902,-1140 4902,-937.17
  text "COMPONENTS MARKED 'DNP' SHOULD NOT BE POPULATED." at 1153.5,-318.5 h60
  text "ASSEMBLY VARIANT:" at 1153,-434 h60
  text ".VariantName" at 2189,-434 h60
  text "PCB VIEWED FROM TOP SIDE" at -228.5,-655.67 h60
  text "BOARD #:" at 2248,-655.67 h60
  text ".PRJ_Number" at 2793.5,-655.67 h60
  text "REV:" at 3638,-655.67 h60
  text ".PCB_Rev" at 3929.5,-655.67 h60
  text "SVN REV:" at 4476,-655.67 h60
  text ".VersionControl_RevNumber" at 4982,-655.67 h60
  text "TID #:" at 2248,-859 h60
  text ".TID" at 2793.5,-859 h60
  text "PLOT NAME =" at -228.5,-1064.34 h60
  text ".plot_File_Name" at 577,-1064.34 h60
  text "GENERATED    :" at 2250,-1064.34 h60
  text ".Print_Date" at 3119.5,-1064.34 h60
  text ".Print_Time" at 3848.5,-1064.34 h60
  text "TEXAS INSTRUMENTS" at 5113,-1064.34 h60
M6 Assembly Bottom:
  lines w10: -292.5,-727.33 6309.5,-727.33 ; -290.5,-930.67 6309.5,-930.67 ; 1115.5,-1140.5 1115.5,-937.67 ; 1737.5,-727.33 1737.5,-524 ; 2577.5,-727.33 2577.5,-524 ; 3844.5,-1134 3844.5,-524 ; 4733.5,-1134 6309,-1134 6309,-524 -292.5,-524 -292.5,-1134 2304.5,-1134 6309.5,-1134 6309.5,-524
  text "COMPONENTS MARKED 'DNP' SHOULD NOT BE POPULATED." at 6102,-318 h60
  text ".VariantName" at 5058,-434 h60
  text "ASSEMBLY VARIANT:" at 6097,-434 h60
  text ".VersionControl_RevNumber" at 1035.5,-656.17 h60
  text "SVN REV:" at 1541.5,-656.17 h60
  text ".PCB_Rev" at 2088,-656.17 h60
  text "REV:" at 2379.5,-656.17 h60
  text ".PRJ_Number" at 3224,-656.17 h60
  text "BOARD #:" at 3769.5,-656.17 h60
  text "PCB VIEWED FROM BOTTOM SIDE" at 6246,-656.17 h60
  text ".TID" at 3224,-859.5 h60
  text "TID #:" at 3769.5,-859.5 h60
  text "TEXAS INSTRUMENTS" at 904.5,-1064.84 h60
  text ".Print_Time" at 2169,-1064.84 h60
  text ".Print_Date" at 2898,-1064.84 h60
  text "GENERATED    :" at 3767.5,-1064.84 h60
  text ".plot_File_Name" at 5440.5,-1064.84 h60
  text "PLOT NAME =" at 6246,-1064.84 h60
M9 Title Sheet:
  drawing of 57 lines, arcs and shapes, not listed
  text "1" at 739.84,8036.5 h70
  text "2" at 3235.5,8036.5 h70
  text "3" at 5724.84,8036.5 h70
  text "4" at 8231.51,8036.5 h70
  text "5" at 10730.5,8036.5 h70
  text "6" at 13235.5,8036.5 h70
  text "A" at -416.5,6893.5 h70
  text "A" at 14383.5,6893.5 h70
  text "B" at -416.5,4513.5 h70
  text "B" at 14383.5,4513.5 h70
  text "C" at -416.5,2138.5 h70
  text "C" at 14383.5,2138.5 h70
  text "PROJECT TITLE:" at 11343.5,277.5 h45
  text ".PRJ_Title" at 11393.5,144.17 h70
  text "DESIGNED FOR:" at 11343.5,-23.5 h45
  text ".PRJ_Customer" at 11393.5,-163.5 h70
  text "D" at -416.5,-231.5 h70
  text "D" at 14383.5,-231.5 h70
  text "FILE NAME:" at 11343.5,-323.5 h45
  text ".PCB_File_Name_No_Path" at 11393.5,-443.5 h70
  text "Texas Instruments (TI) and/or its licensors do not warrant the accuracy or completeness of this specification" at 6374,-605.34 h45
  text "ENGINEER:" at 11343.5,-613.5 h45
  text "LAYOUT BY:" at 12848.5,-613.5 h45
  text "or any information contained therein. TI and/or its licensors do not warrant that this design will meet" at 6329.01,-718 h45
  text ".PRJ_Engineer" at 11393.5,-768.49 h70
  text ".PCB_Layout" at 12899,-768.49 h70
  text "the specifications, will be suitable for your application or fit for any particular purpose, or will operate in" at 6329.01,-830.67 h45
  text ".Layer_Name" at 577,-858.49 h60
  text "ALTIUM DESIGNER VERSION:" at 12848.5,-923.5 h45
  text "an implementation. TI and/or its licensors do not warrant that the design is production worthy. You should" at 6329.01,-943.33 h45
  text "completely validate and test your design implementation to confirm the system functionality for your application." at 6374,-1056 h45
  text ".print_Scale" at 11393.5,-1056.83 h70
  text ".Application_BuildNumber" at 12899,-1056.83 h70
  text "1" at 739.84,-1263.5 h70
  text "2" at 3235.5,-1263.5 h70
  text "3" at 5724.84,-1263.5 h70
  text "4" at 8231.51,-1263.5 h70
  text "5" at 10730.5,-1263.5 h70
  text "6" at 13235.5,-1263.5 h70
M10 Fab Notes:
  drawing of 243 lines, arcs and shapes, not listed
  text "9" at 9505,7420 h40
  text "DESIGN INFORMATION" at 12381.02,6028 h60
  text "MIN. TRACK WIDTH:" at 11736.46,5848 h60
  text "5" at 12832.7,5848 h60
  text "MIL" at 12987.46,5848 h60
  text "MIN. CLEARANCE:" at 11736.46,5716 h60
  text "MIL" at 12987.46,5716 h60
  text "5" at 12850,5700 h60
  text "MIN. VIA PAD SIZE:" at 11736.46,5584 h60
  text "20" at 12802.71,5584 h60
  text "MIL" at 12987.46,5584 h60
  text "0.05mm (2MIL)" at 12431.46,5442.29 h60
  text "MINIMUM ANNULAR RING" at 11407.23,5438 h60
  text "EXTERNAL" at 13139.46,5438 h60
  text "PER" at 11607.23,5320 h60
  text "IPC-D-275 CLASS 2 LEVEL C" at 11827.23,5320 h60
  text "MIL, HOLES" at 13315.46,5207.71 h60
  text "+/-" at 12923,5207 h60
  text "+/-" at 13777,5207 h60
  text "REGISTRATION TOLERANCES:" at 11407.23,5202 h60
  text "METAL" at 12607,5202 h60
  text "5" at 13183.2,5202 h60
  text "3" at 14016.2,5202 h60
  text "MIL" at 14132.46,5202 h60
  text "+/-" at 13777,5089 h60
  text "HOLE SIZE TOLERANCE (UNLESS OTHERWISE SPECIFIED):" at 11407.23,5084 h60
  text "3" at 14016.2,5084 h60
  text "MIL" at 14132.46,5084 h60
  text "MATERIAL:" at 11332.46,4874.54 h60
  text "FR-4 High Tg" at 12318.9,4734.21 h60
  text "FR-408" at 11753.46,4725.64 h60
  text "OTHER" at 13241.46,4725.64 h60
  text "X" at 12164,4722 h60
  text "31MIL +/-10%" at 13673.56,4577.92 h60
  text "62 MIL (1.6mm) +/-10%" at 12073.56,4562.92 h60
  text "X" at 13245,4560 h60
  text "THICKNESS:" at 11407.23,4558.64 h60
  text "OTHER" at 13358.46,4558.64 h60
  text "TOLERANCE:" at 11407.23,4400.64 h60
  text "X" at 12246.53,4400.64 h60
  text "ANSI IPC-6012 TYPE 3 CLASS 2" at 12433.48,4400.64 h60
  text "OTHER +/-" at 12433.46,4244.64 h60
  text "BOW & TWIST:" at 11407.23,4087.64 h60
  text "X" at 12246.53,4087.64 h60
  text "ANSI IPC-6012 TYPE 3 CLASS 2" at 12433.48,4087.64 h60
  text "OTHER +/-" at 12433.46,3929.13 h60
  text "NO SOLDER MASK IN THESE HOLES (TYP)" at 4140,3835 h40
  text "DRILLING:" at 11332.46,3790.64 h60
  text "REFERENCE:" at 11407.23,3673.64 h60
  text "X" at 12055.46,3673.64 h60
  text "AS SHOWN" at 12242.46,3673.64 h60
  text "X" at 12956.46,3673.64 h60
  text "NC_DRILL FILES" at 13093.46,3673.64 h60
  text "9" at 4625,3575 h40
  text "PTH MIN COPPER THICKNESS:" at 11407.23,3515.64 h60
  text "X" at 12757.46,3515.64 h60
  text "1MIL" at 12894.46,3515.64 h60
  text "OTHER" at 13391.46,3515.64 h60
  text "BOARD FINISH:" at 11332.46,3356.64 h60
  text "SILKSCREEN:" at 11487.68,3238.64 h60
  text "X" at 12436.46,3238.64 h60
  text "TOP" at 12562.46,3238.64 h60
  text "X" at 12946.46,3238.64 h60
  text "BOTTOM" at 13073.46,3238.64 h60
  text "TIDA-01102 and TOM spacer Lamination Notes:" at 5858,3160 h80
  text "SILKSCREEN COLOR:" at 11487.68,3071.64 h60
  text "X" at 12435.42,3071.64 h60
  text "WHITE" at 12562.46,3071.64 h60
  text "OTHER" at 13073.46,3071.64 h60
  text "1- LAMINATE FRONT SPACER TO TOP SIDE OF TIDA-01102 BOARD" at 5850,3000 h40
  text "8" at 4615,2995 h40
  text "RED" at 13660,2925 h60
  text "X" at 13155,2915 h60
  text "GREEN" at 12693.46,2912.44 h60
  text "OTHER" at 13311.46,2912.44 h60
  text "SOLDER RESIST COLOR:" at 11487.68,2901.64 h60
  text "2- FRONT SPACER TO BE LAMINATED VERY FLAT." at 5850,2900 h40
  text "3- NO AIR BUBBLES ALLOWED BETWEEN TIDA-01102 AND FRONT SPACER." at 5850,2800 h40
  text "X" at 12566.42,2742.44 h60
  text "MATTE" at 12693.46,2742.44 h60
  text "SEMI-GLOSS" at 13311,2741.8 h60
  text "4- POSITION TIDA01102 AND SPACER CORRECTLY SUCH THAT ALL 20 MIL NON-PLATED HOLES ALIGN." at 5660,2640 h40
  text "5- USE ToM_4X4 FRONT_SPACER_A DATAFILES" at 5840,2590 h40
  text "IMMERSION GOLD (ENIG)" at 12393.46,2553.92 h60
  text "ENEPIG" at 13731,2550.64 h60
  text "SURFACE FINISH:" at 11332.46,2549.64 h60
  text "X" at 12206.51,2549.64 h60
  text "6- The surface must be flat and even on all four corners after lamination." at 5840,2490 h40
  text "7- ACCURACY OF THE NON PLATED HOLE ALIGNMENT IS VERY CRITICAL." at 5840,2400 h40
  text "IMM. TIN/SILVER OR EQUIV" at 11662,2392.64 h60
  text "OTHER" at 13093.46,2392.64 h60
  text "Add top spacer to TIDA-01102 in this location." at 152.29,2349.29 h80
  text "ARRAY/PANEL:" at 11332.46,2213.64 h60
  text "CUT AND TRIM PER M1 BOARD OUTLINE" at 12393.46,2209.35 h60
  text "TOM_4X4_Spacer" at 7530,2130 h40
  text "0.4mm" at 5630,2080 h40
  text "N.C. ROUTE" at 12393.46,2057.64 h60
  text "X" at 13072.46,2057.64 h60
  text "V. SCORE" at 13259.46,2057.64 h60
  text "Prepreg" at 6350,2040 h40
  text "TOP" at 8500,2000 h40
  text "CERTIFICATION:" at 11332.46,1920.64 h60
  text "MATERIALS AND WORKMANSHIP FOR ALL PCBS" at 12057.46,1920.64 h60
  text "Layer2" at 8500,1900 h40
  text "TO MEET OR EXCEED THE REQUIREMENTS OF:" at 12057.46,1822.64 h60
  text "Layer3" at 8500,1800 h40
  text "Bottom" at 8500,1700 h40
  text "X" at 11683.96,1686.13 h60
  text "ANSI IPC-A-600F CLASS ->" at 11822.96,1686.13 h60
  text "X" at 13462.02,1686.13 h60
  text "2" at 13580.96,1686.14 h60
  text "1" at 13265.96,1684.64 h60
  text "3" at 13934.96,1684.64 h60
  text "NO THIEVING (TYP)" at 4315,1580 h40
  text "X" at 11686.02,1526.64 h60
  text "UL 94V-0" at 11822.96,1526.64 h60
  text "X" at 12498.02,1526.64 h60
  text "RoHS" at 12634.96,1526.64 h60
  text "OTHER" at 13279.36,1526.64 h60
  text "PER ORDER" at 13676.42,1526.64 h60
  text "8   -  BOW AND TWIST IS 1.5% FOR THIS BOARD." at 5830,1435 h40
  text "ADDITIONAL REQUIREMENTS:" at 11332.46,1385.64 h60
  text "MICROSECTION:" at 11407.23,1270.64 h60
  text "YES" at 12312.96,1270.64 h60
  text "9   -  SEE LAYER M10 FOR PRECISE LOCATION OF FRONT SPACER." at 5825,1225 h40
  text "REQUIRED" at 13174.46,1114.49 h60
  text "BARE BOARD ELEC. TEST:" at 11407.23,1111.64 h60
  text "NONE" at 12712.96,1111.64 h60
  text "X" at 13047.46,1111.64 h60
  text "PER ORDER" at 13766.46,1111.64 h60
  text "MANUFACTURER'S UL:" at 11407.23,954.64 h60
  text "RAIL" at 12572.96,950.35 h60
  text "METAL" at 13064.77,950.35 h60
  text "X" at 13440,950 h60
  text "SILK" at 13576.46,950.35 h60
  text ".Layer_Name" at 577,-858.49 h60
M11 Gerber Information:
  lines w10: -292,-930.17 6308,-930.17 ; -292,-726.83 6310,-726.83 ; -292,-523.5 -292,-1133.5 3713,-1133.5 6310,-1133.5 6310,-523.5 -291.5,-523.5 -291.5,-1133.5 1284,-1133.5 ; 2173,-1133.5 2173,-523.5 ; 3440,-726.83 3440,-523.5 ; 4280,-726.83 4280,-523.5 ; 4902,-1140 4902,-937.17
  text "ALL ARTWORK VIEWED FROM TOP SIDE" at -228.5,-655.67 h60
  text "BOARD #:" at 2248,-655.67 h60
  text ".PRJ_Number" at 2793.5,-655.67 h60
  text "REV:" at 3638,-655.67 h60
  text ".PCB_Rev" at 3929.5,-655.67 h60
  text "SVN REV:" at 4476,-655.67 h60
  text ".VersionControl_RevNumber" at 4982,-655.67 h60
  text "LAYER NAME =" at -228.5,-858.49 h60
  text "TID #:" at 2248,-859 h60
  text ".TID" at 2793.5,-859 h60
  text "PLOT NAME =" at -228.5,-1064.34 h60
  text ".plot_File_Name" at 577,-1064.34 h60
  text "GENERATED    :" at 2250,-1064.34 h60
  text ".Print_Date" at 3119.5,-1064.34 h60
  text ".Print_Time" at 3848.5,-1064.34 h60
  text "TEXAS INSTRUMENTS" at 5113,-1064.34 h60
M12 Stackup:
  drawing of 295 lines, arcs and shapes, not listed
  text "Layer" at 9666.2,7760 h60
  text "Name" at 10076.11,7760 h60
  text "Material" at 11005.85,7760 h60
  text "Thickness" at 11865.62,7760 h60
  text "Constant" at 12515.46,7760 h60
  text "Board Layer Stack" at 13085.32,7760 h60
  text "1" at 9666.2,7640 h60
  text "Top Overlay" at 10076.11,7640 h60
  text "2" at 9666.2,7520 h60
  text "Top Solder" at 10076.11,7520 h60
  text "Solder Resist" at 11005.85,7520 h60
  text "0.40mil" at 11865.62,7520 h60
  text "3.5" at 12515.46,7520 h60
  text "3" at 9666.2,7400 h60
  text "Top Layer" at 10076.11,7400 h60
  text "Copper" at 11005.85,7400 h60
  text "1.30mil" at 11865.62,7400 h60
  text "4" at 9666.2,7280 h60
  text "Dielectric1" at 10076.11,7280 h60
  text "FR-4" at 11005.85,7280 h60
  text "5.50mil" at 11865.62,7280 h60
  text "4.1" at 12515.46,7280 h60
  text "5" at 9666.2,7160 h60
  text "Mid-Layer 1" at 10076.11,7160 h60
  text "Copper" at 11005.85,7160 h60
  text "1.40mil" at 11865.62,7160 h60
  text "6" at 9666.2,7040 h60
  text "Dielectric2" at 10076.11,7040 h60
  text "FR-4" at 11005.85,7040 h60
  text "12.90mil" at 11865.62,7040 h60
  text "4.1" at 12515.46,7040 h60
  text "7" at 9666.2,6920 h60
  text "Mid-Layer 2" at 10076.11,6920 h60
  text "Copper" at 11005.85,6920 h60
  text "1.40mil" at 11865.62,6920 h60
  text "8" at 9666.2,6800 h60
  text "Dielectric3" at 10076.11,6800 h60
  text "FR-4" at 11005.85,6800 h60
  text "5.50mil" at 11865.62,6800 h60
  text "4.1" at 12515.46,6800 h60
  text "9" at 9666.2,6680 h60
  text "Bottom Layer" at 10076.11,6680 h60
  text "Copper" at 11005.85,6680 h60
  text "1.30mil" at 11865.62,6680 h60
  text "10" at 9666.2,6560 h60
  text "Bottom Solder" at 10076.11,6560 h60
  text "Solder Resist" at 11005.85,6560 h60
  text "0.40mil" at 11865.62,6560 h60
  text "3.5" at 12515.46,6560 h60
  text "11" at 9666.2,6440 h60
  text "Bottom Overlay" at 10076.11,6440 h60
  text ".Layer_Name" at 577,-858.49 h60
M13 Component Bodies Top:
  text ".Layer_Name" at 577,-858.49 h60
M14 Component Bodies Bottom:
  text ".Layer_Name" at 577,-858.49 h60
M15 Courtyards Top:
  text "M15-" at 577,-858.49 h60
M16 Courtyards Bottom:
  text ".Layer_Name" at 577,-858.49 h60
Drill Drawing:
  circle w10: c5318.72,6521.36 r16.58
  circle w10: c5318.72,6521.36 r27.63
  lines w1: -0.09,4004.56 -0.06,4004.56 ; 0,0 0.03,0 ; 0,15 0.03,15 ; 0,4685 0.03,4685 ; 3998.66,4000.05 3998.69,4000.05 ; 4000.01,-0.01 4000.04,-0.01 ; 4000.04,3993.71 4000.07,3993.71
  lines w10: 5291.09,6618.06 5318.72,6631.87 5346.34,6618.06 5332.53,6645.68 5346.34,6673.31 5318.72,6659.5 5291.09,6673.31 5304.9,6645.68 5291.09,6618.06 ; 5291.09,6742.38 5291.09,6756.19 5304.9,6770 5291.09,6783.82 5291.09,6797.63 5304.9,6797.63 5318.72,6783.82 5332.53,6797.63 5346.34,6797.63 5346.34,6783.82 5332.53,6770 5346.34,6756.19 5346.34,6742.38 5332.53,6742.38 5318.72,6756.19 5304.9,6742.38 5291.09,6742.38 ; 5291.09,6880.51 5304.9,6880.51 5304.9,6866.7 5332.53,6866.7 5332.53,6880.51 5346.34,6880.51 5346.34,6908.14 5332.53,6908.14 5332.53,6921.95 5304.9,6921.95 5304.9,6908.14 5291.09,6908.14 5291.09,6880.51 ; 5291.09,6991.02 5346.34,6991.02 5346.34,7046.27 5291.09,7046.27 5291.09,6991.02 ; 5291.09,7253.47 5304.9,7253.47 5318.72,7239.66 5332.53,7253.47 5346.34,7253.47 5332.53,7267.28 5346.34,7281.1 5332.53,7281.1 5318.72,7294.91 5304.9,7281.1 5291.09,7281.1 5304.9,7267.28 5291.09,7253.47 ; 5291.09,7363.98 5346.34,7363.98 5346.34,7419.23 5291.09,7419.23 5291.09,7363.98 ; 5302.14,6629.11 5318.72,6637.4 5335.29,6629.11 5327.01,6645.68 5335.29,6662.26 5318.72,6653.97 5302.14,6662.26 5310.43,6645.68 5302.14,6629.11 ; 5302.14,6753.43 5302.14,6761.72 5310.43,6770 5302.14,6778.29 5302.14,6786.58 5310.43,6786.58 5318.72,6778.29 5327.01,6786.58 5335.29,6786.58 5335.29,6778.29 5327.01,6770 5335.29,6761.72 5335.29,6753.43 5327.01,6753.43 5318.72,6761.72 5310.43,6753.43 5302.14,6753.43 ; 5302.14,6886.04 5310.43,6886.04 5310.43,6877.75 5327.01,6877.75 5327.01,6886.04 5335.29,6886.04 5335.29,6902.61 5327.01,6902.61 5327.01,6910.9 5310.43,6910.9 5310.43,6902.61 5302.14,6902.61 5302.14,6886.04 ; 5302.14,7002.07 5335.29,7002.07 5335.29,7035.22 5302.14,7035.22 5302.14,7002.07 ; 5302.14,7259 5310.43,7259 5318.72,7250.71 5327.01,7259 5335.29,7259 5327.01,7267.28 5335.29,7275.57 5327.01,7275.57 5318.72,7283.86 5310.43,7275.57 5302.14,7275.57 5310.43,7267.28 5302.14,7259
  lines w12: 5241,6456.44 9035.76,6456.44 ; 5241,7451 9035.76,7451 ; 5578.86,6332.12 5578.86,7575.32 ; 5910.86,6332.12 5910.86,7575.32 ; 6547.43,6332.12 6547.43,7575.32 ; 6806.57,6332.12 6806.57,7575.32 ; 7181.72,6332.12 7181.72,7575.32 ; 7906.05,6332.12 7906.05,7575.32 ; 8435.19,6332.12 8435.19,7575.32 ; 5241,6332.12 9035.76,6332.12 9035.76,7575.32 5241,7575.32 5241,6332.12
  text "Symbol" at 5315.59,7488.3 h72
  text "Quantity" at 5616.16,7488.3 h72
  text "Finished Hole Size" at 5948.16,7488.3 h72
  text "Plated" at 6584.72,7488.3 h72
  text "Hole Type" at 6843.86,7488.3 h72
  text "Drill Layer Pair" at 7219.02,7488.3 h72
  text "Hole Tolerance" at 7943.35,7488.3 h72
  text "Hole Length" at 8472.49,7488.3 h72
  text "377" at 5616.16,7363.98 h60
  text "20.00mil (0.508mm)" at 5948.16,7363.98 h60
  text "NPTH" at 6584.72,7363.98 h60
  text "Round" at 6843.86,7363.98 h60
  text "Top Layer - Bottom Layer" at 7219.02,7363.98 h60
  text "-" at 8472.49,7363.98 h60
  text "1" at 5616.16,7239.66 h60
  text "25.00mil (0.635mm)" at 5948.16,7239.66 h60
  text "NPTH" at 6584.72,7239.66 h60
  text "Round" at 6843.86,7239.66 h60
  text "Top Layer - Bottom Layer" at 7219.02,7239.66 h60
  text "-" at 8472.49,7239.66 h60
  text "5" at 5616.16,7115.34 h60
  text "7.87mil (0.200mm)" at 5948.16,7115.34 h60
  text "PTH" at 6584.72,7115.34 h60
  text "Round" at 6843.86,7115.34 h60
  text "Top Layer - Bottom Layer" at 7219.02,7115.34 h60
  text "-" at 8472.49,7115.34 h60
  text "A" at 5290.31,7105.35 h55.25
  text "281" at 5616.16,6991.02 h60
  text "10.00mil (0.254mm)" at 5948.16,6991.02 h60
  text "PTH" at 6584.72,6991.02 h60
  text "Round" at 6843.86,6991.02 h60
  text "Top Layer - Bottom Layer" at 7219.02,6991.02 h60
  text "-" at 8472.49,6991.02 h60
  text "2" at 5616.16,6866.7 h60
  text "19.69mil (0.500mm)" at 5948.16,6866.7 h60
  text "PTH" at 6584.72,6866.7 h60
  text "Round" at 6843.86,6866.7 h60
  text "Top Layer - Bottom Layer" at 7219.02,6866.7 h60
  text "-" at 8472.49,6866.7 h60
  text "5" at 5616.16,6742.38 h60
  text "24.00mil (0.610mm)" at 5948.16,6742.38 h60
  text "PTH" at 6584.72,6742.38 h60
  text "Round" at 6843.86,6742.38 h60
  text "Top Layer - Bottom Layer" at 7219.02,6742.38 h60
  text "-" at 8472.49,6742.38 h60
  text "3" at 5616.16,6618.06 h60
  text "40.00mil (1.016mm)" at 5948.16,6618.06 h60
  text "PTH" at 6584.72,6618.06 h60
  text "Round" at 6843.86,6618.06 h60
  text "Top Layer - Bottom Layer" at 7219.02,6618.06 h60
  text "-" at 8472.49,6618.06 h60
  text "2" at 5616.16,6493.74 h60
  text "19.69mil (0.500mm)" at 5948.16,6493.74 h60
  text "PTH" at 6584.72,6493.74 h60
  text "Slot" at 6843.86,6493.74 h60
  text "Top Layer - Bottom Layer" at 7219.02,6493.74 h60
  text "47.24mil (1.200mm)" at 8472.49,6493.74 h60
  text "676 Total" at 5616.16,6369.42 h60
  text "Slot definitions :" at 5315.59,6282.39 h60
  text "Routed Path Length" at 5766.31,6282.39 h60
  text "= Calculated from tool start centre position to tool end centre position." at 6306.05,6282.39 h60
  text "Hole Length" at 5766.31,6232.67 h60
  text "= Routed Path Length + Tool Size = Slot length as defined in the PCB layout" at 6106.24,6232.67 h60
  text ".Layer_Name" at 577,-858.49 h60

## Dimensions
4000,0 to 4000,5050 on M2 Board Dimensions
0,-400 to 1000,-400 on M2 Board Dimensions
0,0 to 4000,0 on M2 Board Dimensions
